FUNCTION "Output Linea e Boxing_2R" : VOID
TITLE =Gestione Output
AUTHOR : MassimoZ
FAMILY : NovaSrl
VERSION : 0.1

BEGIN
NETWORK
TITLE =R0 = Ripristino Emergenza

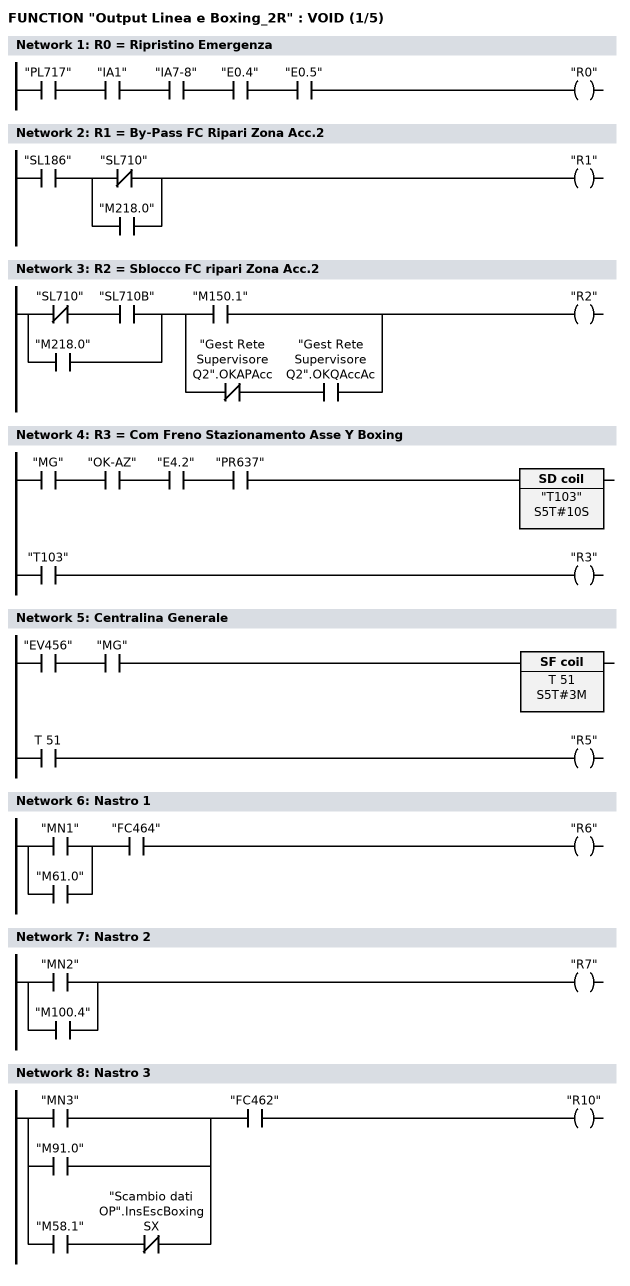
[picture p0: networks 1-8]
      U     "PL717";
      U     "IA1";
      U     "IA7-8";
      U     "E0.4";
      U     "E0.5";
      =     "R0";
NETWORK
TITLE =R1 = By-Pass FC Ripari Zona Acc.2

      U     "SL186";
      U(    ;
      ON    "SL710";
      O     "M218.0";
      )     ;
      =     "R1";
NETWORK
TITLE =R2 = Sblocco FC ripari Zona Acc.2

      U(    ;
      UN    "SL710";
      U     "SL710B";
      O     "M218.0";
      )     ;
      U(    ;
      O     "M150.1";
      O     ;
      UN    "Gest Rete Supervisore Q2".OKAPAcc;
      U     "Gest Rete Supervisore Q2".OKQAccAc;
      )     ;
      =     "R2";
NETWORK
TITLE =R3 = Com Freno Stazionamento Asse Y Boxing

      U     "MG";
      U     "OK-AZ";
      U     "E4.2";
      U     "PR637";
      L     S5T#10S;
      SE    "T103";
      NOP   0;
      NOP   0;
      NOP   0;
      U     "T103";
      =     "R3";
NETWORK
TITLE =Centralina Generale

      U     "EV456";
      U     "MG";
      L     S5T#3M;
      SA    T     51;
      NOP   0;
      NOP   0;
      NOP   0;
      U     T     51;
      =     "R5";
NETWORK
TITLE =Nastro 1

      U(    ;
      O     "MN1";
      O     "M61.0";
      )     ;
      U     "FC464";
      =     "R6";
NETWORK
TITLE =Nastro 2

      O     "MN2";
      O     "M100.4";
      =     "R7";
NETWORK
TITLE =Nastro 3

      U(    ;
      O     "MN3";
      O     "M91.0";
      O     ;
      U     "M58.1";
      UN    "Scambio dati OP".InsEscBoxingSX;
      )     ;
      U     "FC462";
      =     "R10";
NETWORK
TITLE =R11 = Abilitazione Asse X Boxing

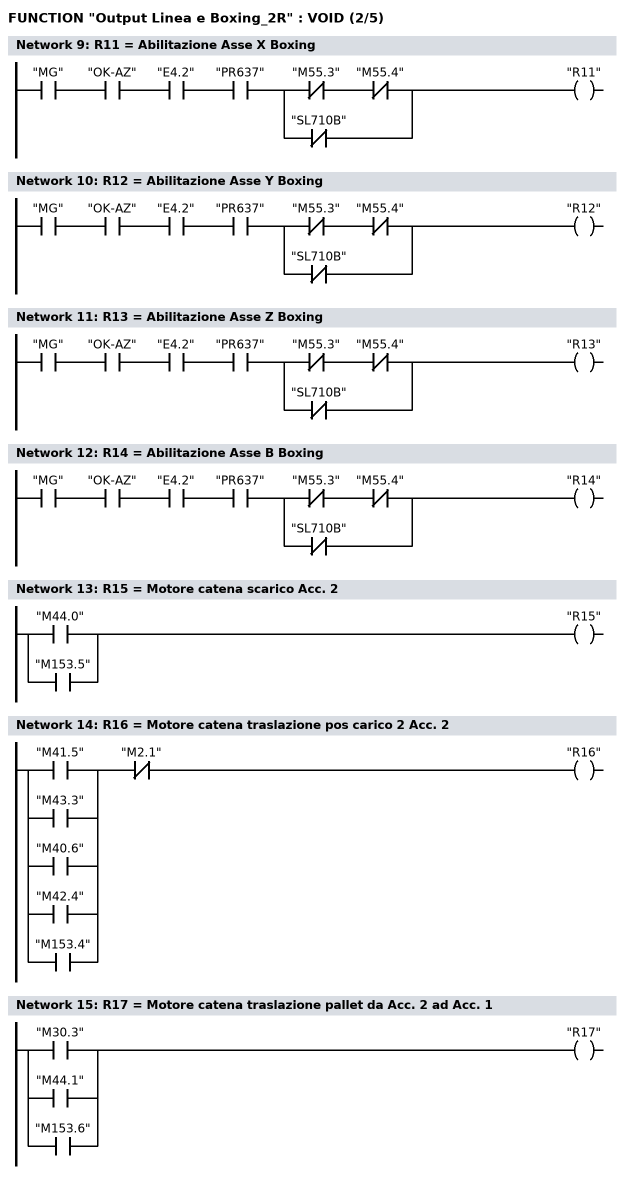
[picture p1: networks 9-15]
      U     "MG";
      U     "OK-AZ";
      U     "E4.2";
      U     "PR637";
      U(    ;
      UN    "M55.3";
      UN    "M55.4";
      ON    "SL710B";
      )     ;
      =     "R11";
NETWORK
TITLE =R12 = Abilitazione Asse Y Boxing

      U     "MG";
      U     "OK-AZ";
      U     "E4.2";
      U     "PR637";
      U(    ;
      UN    "M55.3";
      UN    "M55.4";
      ON    "SL710B";
      )     ;
      =     "R12";
NETWORK
TITLE =R13 = Abilitazione Asse Z Boxing

      U     "MG";
      U     "OK-AZ";
      U     "E4.2";
      U     "PR637";
      U(    ;
      UN    "M55.3";
      UN    "M55.4";
      ON    "SL710B";
      )     ;
      =     "R13";
NETWORK
TITLE =R14 = Abilitazione Asse B Boxing

      U     "MG";
      U     "OK-AZ";
      U     "E4.2";
      U     "PR637";
      U(    ;
      UN    "M55.3";
      UN    "M55.4";
      ON    "SL710B";
      )     ;
      =     "R14";
NETWORK
TITLE =R15 = Motore catena scarico Acc. 2

      O     "M44.0";
      O     "M153.5";
      =     "R15";
NETWORK
TITLE =R16 = Motore catena traslazione pos carico 2 Acc. 2

      U(    ;
      O     "M41.5";
      O     "M43.3";
      O     "M40.6";
      O     "M42.4";
      O     "M153.4";
      )     ;
      UN    "M2.1";
      =     "R16";
NETWORK
TITLE =R17 = Motore catena traslazione pallet da Acc. 2 ad Acc. 1

      O     "M30.3";
      O     "M44.1";
      O     "M153.6";
      =     "R17";
NETWORK
TITLE =R20 = Motore catena traslazione pos carico 2 Acc. 1

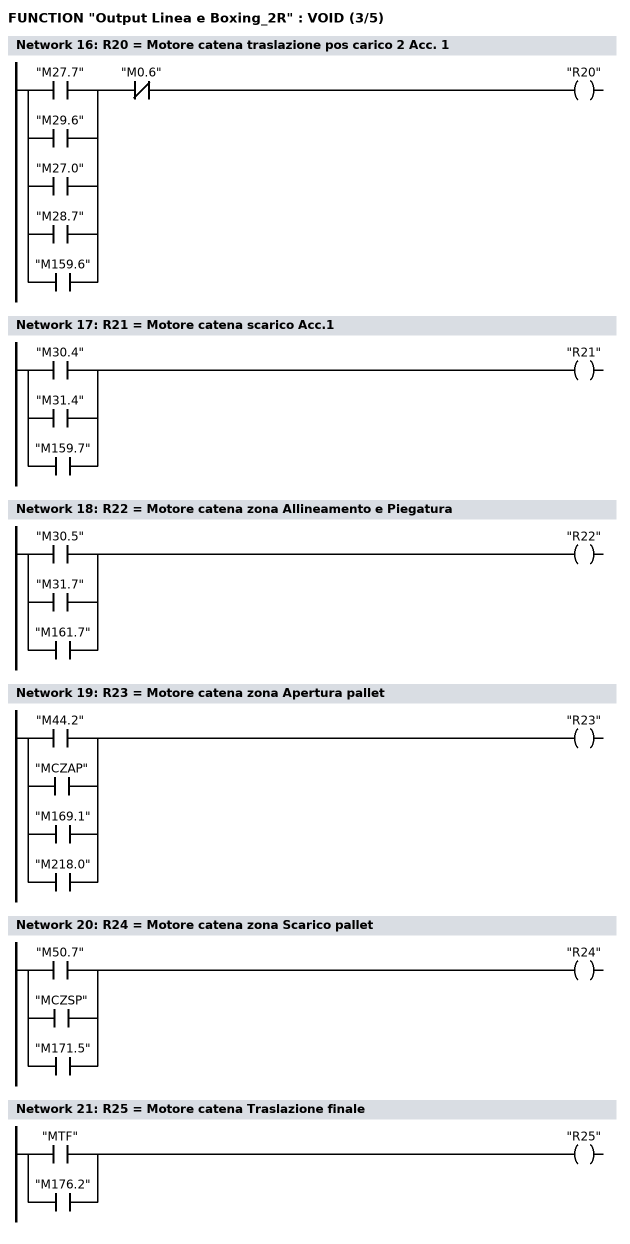
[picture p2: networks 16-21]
      U(    ;
      O     "M27.7";
      O     "M29.6";
      O     "M27.0";
      O     "M28.7";
      O     "M159.6";
      )     ;
      UN    "M0.6";
      =     "R20";
NETWORK
TITLE =R21 = Motore catena scarico Acc.1

      O     "M30.4";
      O     "M31.4";
      O     "M159.7";
      =     "R21";
NETWORK
TITLE =R22 = Motore catena zona Allineamento e Piegatura

      O     "M30.5";
      O     "M31.7";
      O     "M161.7";
      =     "R22";
NETWORK
TITLE =R23 = Motore catena zona Apertura pallet

      O     "M44.2";
      O     "MCZAP";
      O     "M169.1";
      O     "M218.0";
      =     "R23";
NETWORK
TITLE =R24 = Motore catena zona Scarico pallet

      O     "M50.7";
      O     "MCZSP";
      O     "M171.5";
      =     "R24";
NETWORK
TITLE =R25 = Motore catena Traslazione finale

      O     "MTF";
      O     "M176.2";
      =     "R25";
NETWORK
TITLE =R26 = Motore catena Alimentazione accatastatrici

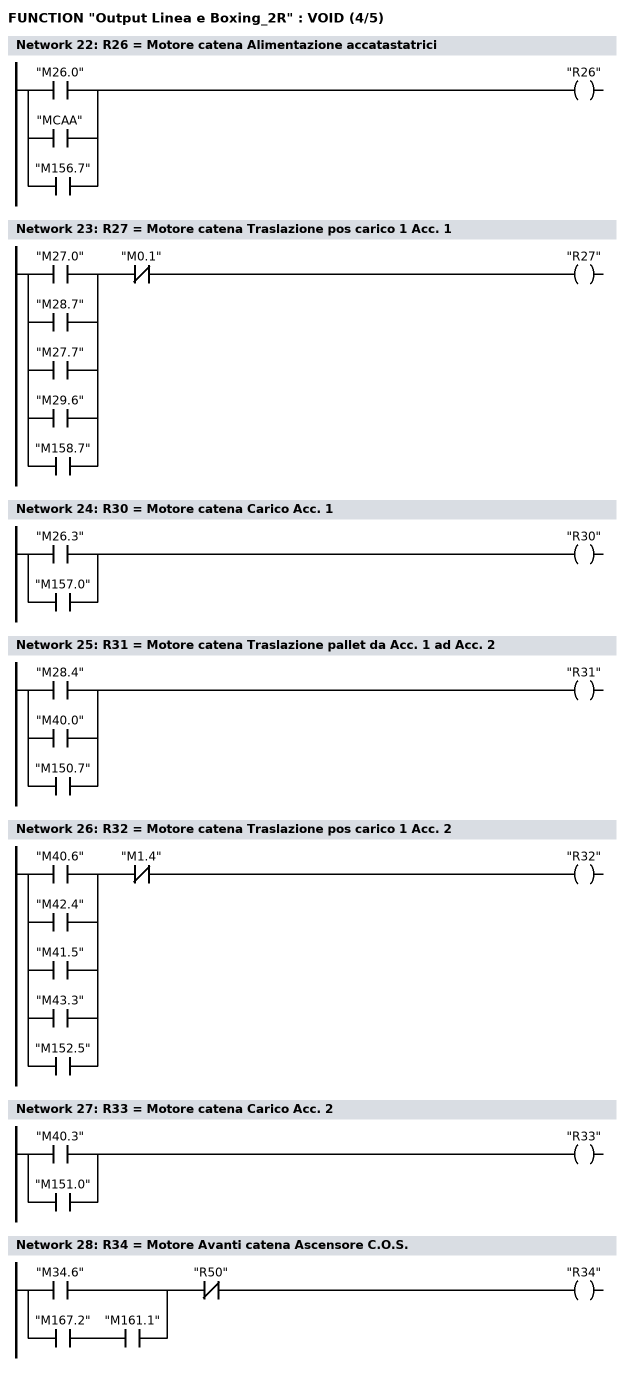
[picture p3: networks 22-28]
      O     "M26.0";
      O     "MCAA";
      O     "M156.7";
      =     "R26";
NETWORK
TITLE =R27 = Motore catena Traslazione pos carico 1 Acc. 1

      U(    ;
      O     "M27.0";
      O     "M28.7";
      O     "M27.7";
      O     "M29.6";
      O     "M158.7";
      )     ;
      UN    "M0.1";
      =     "R27";
NETWORK
TITLE =R30 = Motore catena Carico Acc. 1

      O     "M26.3";
      O     "M157.0";
      =     "R30";
NETWORK
TITLE =R31 = Motore catena Traslazione pallet da Acc. 1 ad Acc. 2

      O     "M28.4";
      O     "M40.0";
      O     "M150.7";
      =     "R31";
NETWORK
TITLE =R32 = Motore catena Traslazione pos carico 1 Acc. 2

      U(    ;
      O     "M40.6";
      O     "M42.4";
      O     "M41.5";
      O     "M43.3";
      O     "M152.5";
      )     ;
      UN    "M1.4";
      =     "R32";
NETWORK
TITLE =R33 = Motore catena Carico Acc. 2

      O     "M40.3";
      O     "M151.0";
      =     "R33";
NETWORK
TITLE =R34 = Motore Avanti catena Ascensore C.O.S.

      U(    ;
      O     "M34.6";
      O     ;
      U     "M167.2";
      U     "M161.1";
      )     ;
      UN    "R50";
      =     "R34";
NETWORK
TITLE =R35 = Motore catena Traslatore scarico SX Avanti

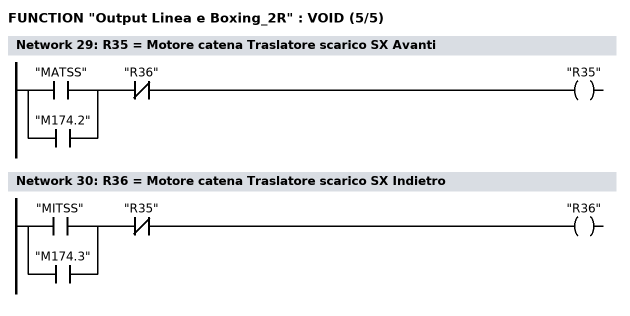
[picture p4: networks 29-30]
      U(    ;
      O     "MATSS";
      O     "M174.2";
      )     ;
      UN    "R36";
      =     "R35";
NETWORK
TITLE =R36 = Motore catena Traslatore scarico SX Indietro

      U(    ;
      O     "MITSS";
      O     "M174.3";
      )     ;
      UN    "R35";
      =     "R36";
NETWORK
TITLE =R37 = Scorta

      CLR   ;
      =     "R37";
NETWORK
TITLE =R40 = Motore catena Traslatore scarico DX Avanti

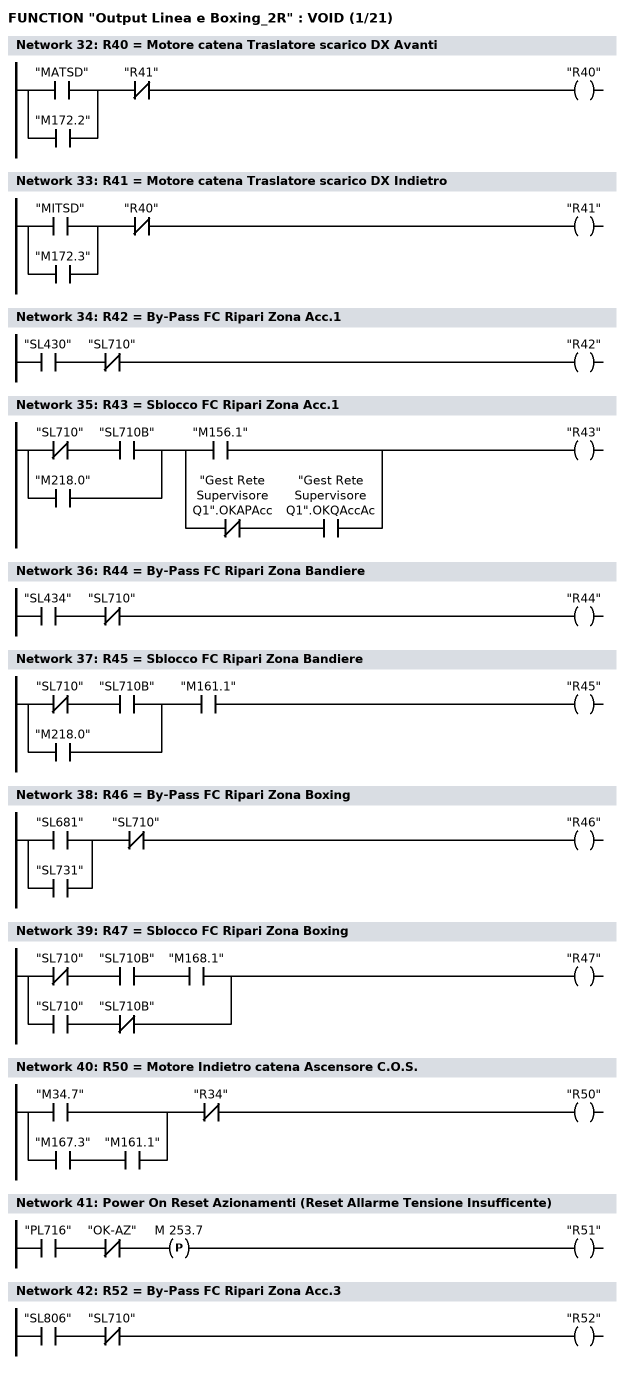
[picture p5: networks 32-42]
      U(    ;
      O     "MATSD";
      O     "M172.2";
      )     ;
      UN    "R41";
      =     "R40";
NETWORK
TITLE =R41 = Motore catena Traslatore scarico DX Indietro

      U(    ;
      O     "MITSD";
      O     "M172.3";
      )     ;
      UN    "R40";
      =     "R41";
NETWORK
TITLE =R42 = By-Pass FC Ripari Zona Acc.1

      U     "SL430";
      UN    "SL710";
      =     "R42";
NETWORK
TITLE =R43 = Sblocco FC Ripari Zona Acc.1

      U(    ;
      UN    "SL710";
      U     "SL710B";
      O     "M218.0";
      )     ;
      U(    ;
      O     "M156.1";
      O     ;
      UN    "Gest Rete Supervisore Q1".OKAPAcc;
      U     "Gest Rete Supervisore Q1".OKQAccAc;
      )     ;
      =     "R43";
NETWORK
TITLE =R44 = By-Pass FC Ripari Zona Bandiere

      U     "SL434";
      UN    "SL710";
      =     "R44";
NETWORK
TITLE =R45 = Sblocco FC Ripari Zona Bandiere

      U(    ;
      UN    "SL710";
      U     "SL710B";
      O     "M218.0";
      )     ;
      U     "M161.1";
      =     "R45";
NETWORK
TITLE =R46 = By-Pass FC Ripari Zona Boxing

      U(    ;
      O     "SL681";
      O     "SL731";
      )     ;
      UN    "SL710";
      =     "R46";
NETWORK
TITLE =R47 = Sblocco FC Ripari Zona Boxing

      UN    "SL710";
      U     "SL710B";
      U     "M168.1";
      O     ;
      U     "SL710";
      UN    "SL710B";
      =     "R47";
NETWORK
TITLE =R50 = Motore Indietro catena Ascensore C.O.S.

      U(    ;
      O     "M34.7";
      O     ;
      U     "M167.3";
      U     "M161.1";
      )     ;
      UN    "R34";
      =     "R50";
NETWORK
TITLE =Power On Reset Azionamenti (Reset Allarme Tensione Insufficente)

      U     "PL716";
      UN    "OK-AZ";
      FP    M    253.7;
      =     "R51";
NETWORK
TITLE =R52 = By-Pass FC Ripari Zona Acc.3

      U     "SL806";
      UN    "SL710";
      =     "R52";
NETWORK
TITLE =R50 = Sblocco FC Ripari Zona Acc.3

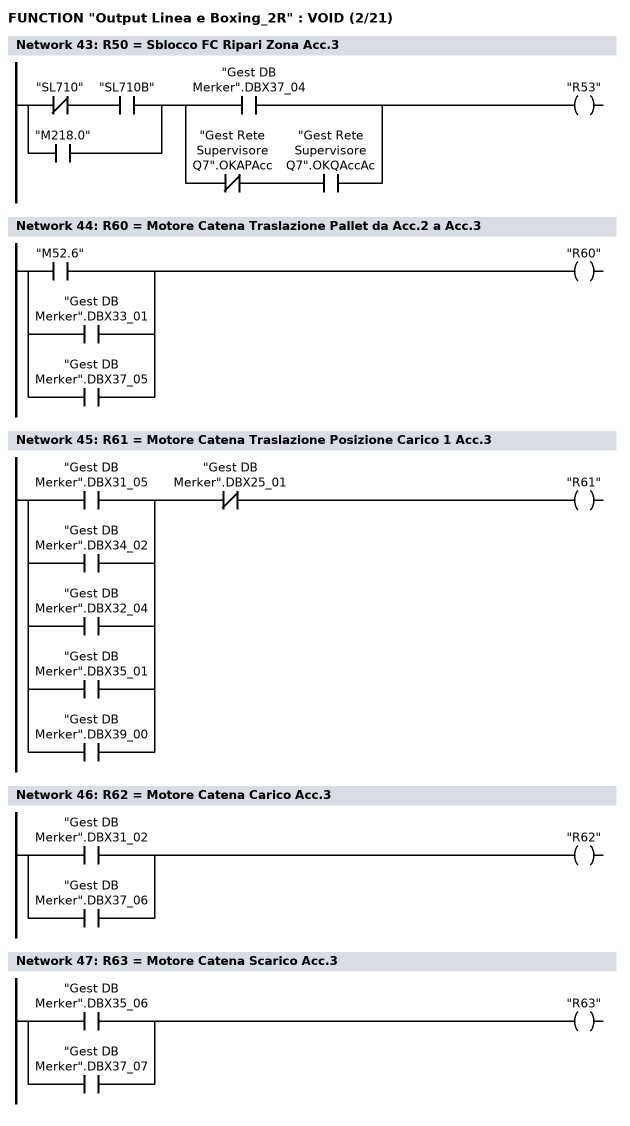
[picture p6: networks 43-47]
      U(    ;
      UN    "SL710";
      U     "SL710B";
      O     "M218.0";
      )     ;
      U(    ;
      O     "Gest DB Merker".DBX37_04;
      O     ;
      UN    "Gest Rete Supervisore Q7".OKAPAcc;
      U     "Gest Rete Supervisore Q7".OKQAccAc;
      )     ;
      =     "R53";
NETWORK
TITLE =R60 = Motore Catena Traslazione Pallet da Acc.2 a Acc.3

      O     "M52.6";
      O     "Gest DB Merker".DBX33_01;
      O     "Gest DB Merker".DBX37_05;
      =     "R60";
NETWORK
TITLE =R61 = Motore Catena Traslazione Posizione Carico 1 Acc.3

      U(    ;
      O     "Gest DB Merker".DBX31_05;
      O     "Gest DB Merker".DBX34_02;
      O     "Gest DB Merker".DBX32_04;
      O     "Gest DB Merker".DBX35_01;
      O     "Gest DB Merker".DBX39_00;
      )     ;
      UN    "Gest DB Merker".DBX25_01;
      =     "R61";
NETWORK
TITLE =R62 = Motore Catena Carico Acc.3

      O     "Gest DB Merker".DBX31_02;
      O     "Gest DB Merker".DBX37_06;
      =     "R62";
NETWORK
TITLE =R63 = Motore Catena Scarico Acc.3

      O     "Gest DB Merker".DBX35_06;
      O     "Gest DB Merker".DBX37_07;
      =     "R63";
NETWORK
TITLE =R64 = Motore Catena Traslazione Posizione Carico 2 Acc.3

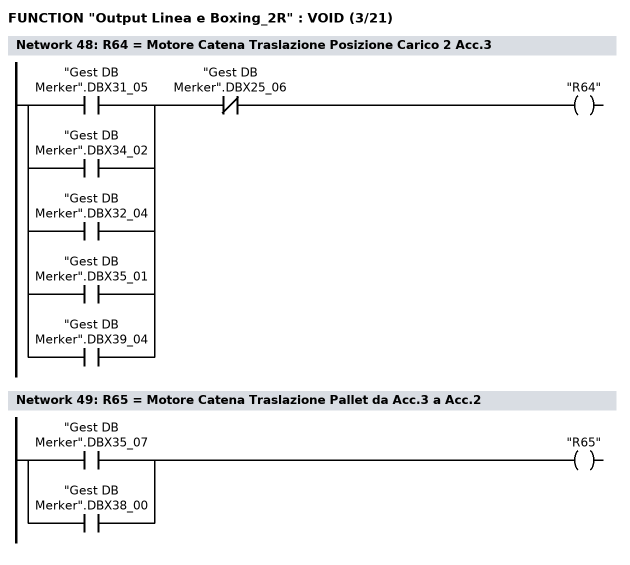
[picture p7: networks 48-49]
      U(    ;
      O     "Gest DB Merker".DBX31_05;
      O     "Gest DB Merker".DBX34_02;
      O     "Gest DB Merker".DBX32_04;
      O     "Gest DB Merker".DBX35_01;
      O     "Gest DB Merker".DBX39_04;
      )     ;
      UN    "Gest DB Merker".DBX25_06;
      =     "R64";
NETWORK
TITLE =R65 = Motore Catena Traslazione Pallet da Acc.3 a Acc.2

      O     "Gest DB Merker".DBX35_07;
      O     "Gest DB Merker".DBX38_00;
      =     "R65";
NETWORK
TITLE =Traslazione Pinze Polso Avanti

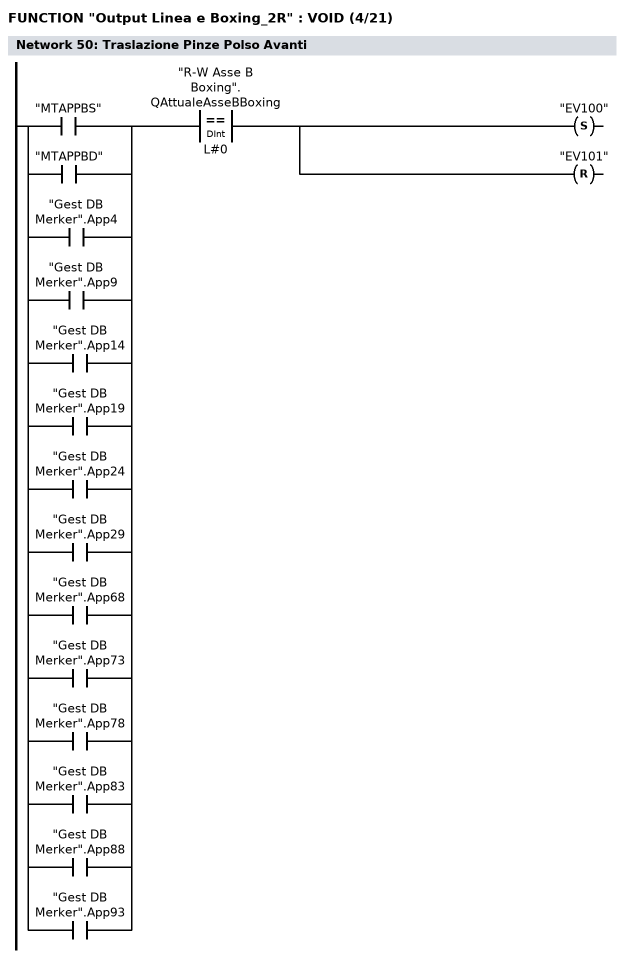
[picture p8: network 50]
      U(    ;
      O     "MTAPPBS";
      O     "MTAPPBD";
      O     "Gest DB Merker".App4;
      O     "Gest DB Merker".App9;
      O     "Gest DB Merker".App14;
      O     "Gest DB Merker".App19;
      O     "Gest DB Merker".App24;
      O     "Gest DB Merker".App29;
      O     "Gest DB Merker".App68;
      O     "Gest DB Merker".App73;
      O     "Gest DB Merker".App78;
      O     "Gest DB Merker".App83;
      O     "Gest DB Merker".App88;
      O     "Gest DB Merker".App93;
      )     ;
      U(    ;
      L     "R-W Asse B Boxing".QAttualeAsseBBoxing;
      L     L#0;
      ==D   ;
      )     ;
      S     "EV100";
      R     "EV101";
NETWORK
TITLE =Traslazione Pinze Polso Indietro

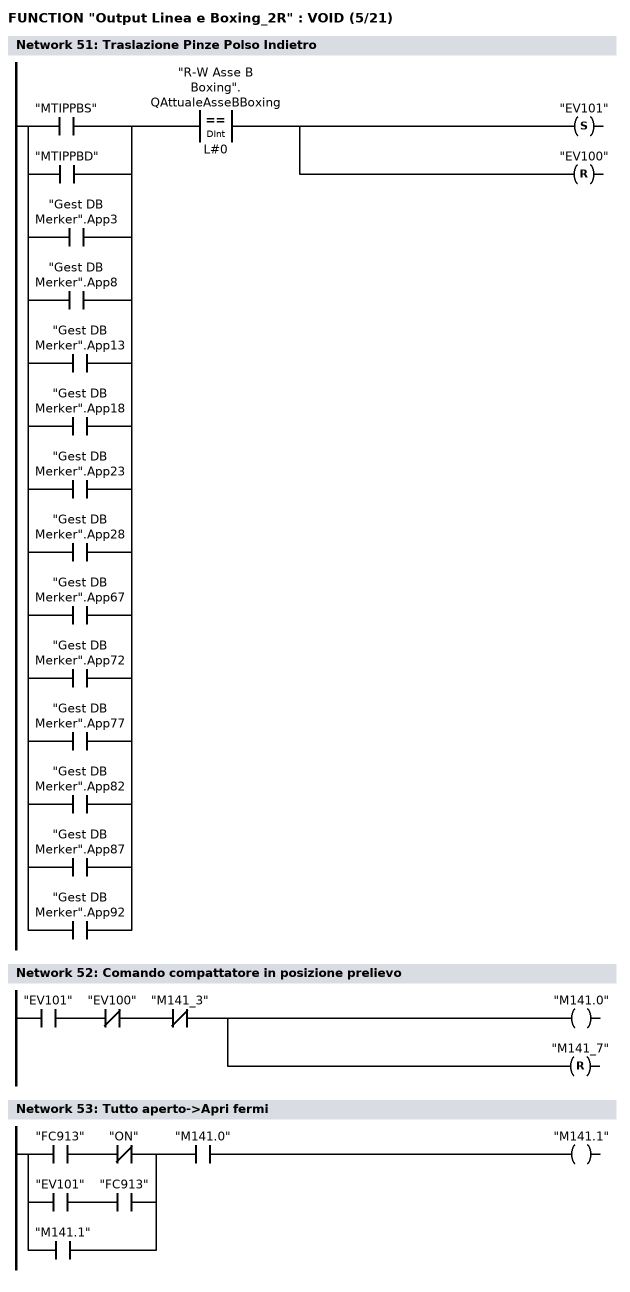
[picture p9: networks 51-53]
      U(    ;
      O     "MTIPPBS";
      O     "MTIPPBD";
      O     "Gest DB Merker".App3;
      O     "Gest DB Merker".App8;
      O     "Gest DB Merker".App13;
      O     "Gest DB Merker".App18;
      O     "Gest DB Merker".App23;
      O     "Gest DB Merker".App28;
      O     "Gest DB Merker".App67;
      O     "Gest DB Merker".App72;
      O     "Gest DB Merker".App77;
      O     "Gest DB Merker".App82;
      O     "Gest DB Merker".App87;
      O     "Gest DB Merker".App92;
      )     ;
      U(    ;
      L     "R-W Asse B Boxing".QAttualeAsseBBoxing;
      L     L#0;
      ==D   ;
      )     ;
      S     "EV101";
      R     "EV100";
NETWORK
TITLE =Comando compattatore in posizione prelievo

      U     "EV101";
      UN    "EV100";
      UN    "M141_3";
      =     "M141.0";
      R     "M141_7";
NETWORK
TITLE =Tutto aperto->Apri fermi

      U(    ;
      U     "FC913";
      UN    "ON";
      O     ;
      U     "EV101";
      U     "FC913";
      O     "M141.1";
      )     ;
      U     "M141.0";
      =     "M141.1";
NETWORK
TITLE =Fermi aperti->richiudi

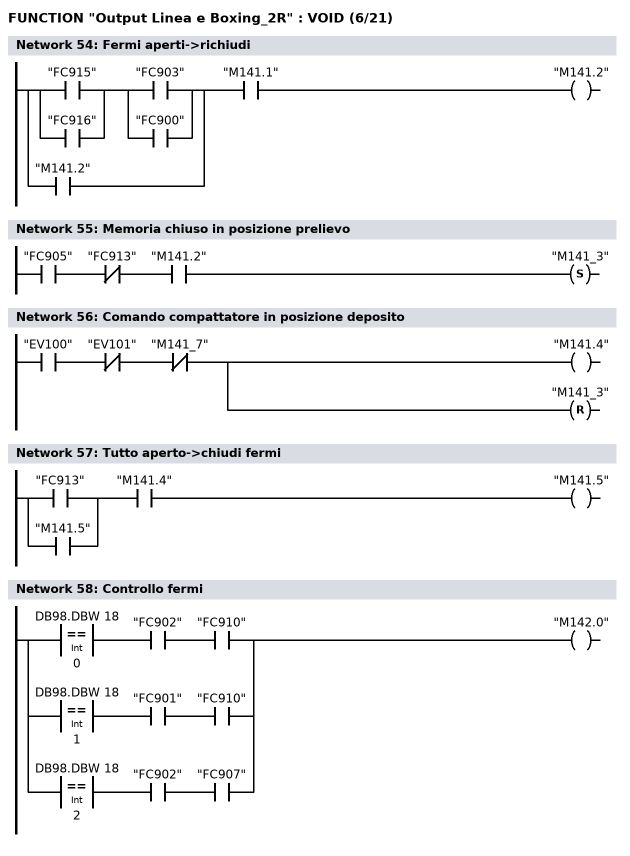
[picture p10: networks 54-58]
      U(    ;
      U(    ;
      O     "FC915";
      O     "FC916";
      )     ;
      U(    ;
      O     "FC903";
      O     "FC900";
      )     ;
      O     "M141.2";
      )     ;
      U     "M141.1";
      =     "M141.2";
NETWORK
TITLE =Memoria chiuso in posizione prelievo

      U     "FC905";
      UN    "FC913";
      U     "M141.2";
      S     "M141_3";
NETWORK
TITLE =Comando compattatore in posizione deposito

      U     "EV100";
      UN    "EV101";
      UN    "M141_7";
      =     "M141.4";
      R     "M141_3";
NETWORK
TITLE =Tutto aperto->chiudi fermi

      U(    ;
      O     "FC913";
      O     "M141.5";
      )     ;
      U     "M141.4";
      =     "M141.5";
NETWORK
TITLE =Controllo fermi

      U(    ;
      L     DB98.DBW   18;
      L     0;
      ==I   ;
      )     ;
      U     "FC902";
      U     "FC910";
      O     ;
      U(    ;
      L     DB98.DBW   18;
      L     1;
      ==I   ;
      )     ;
      U     "FC901";
      U     "FC910";
      O     ;
      U(    ;
      L     DB98.DBW   18;
      L     2;
      ==I   ;
      )     ;
      U     "FC902";
      U     "FC907";
      =     "M142.0";
NETWORK
TITLE =Controllo rotazione pinze

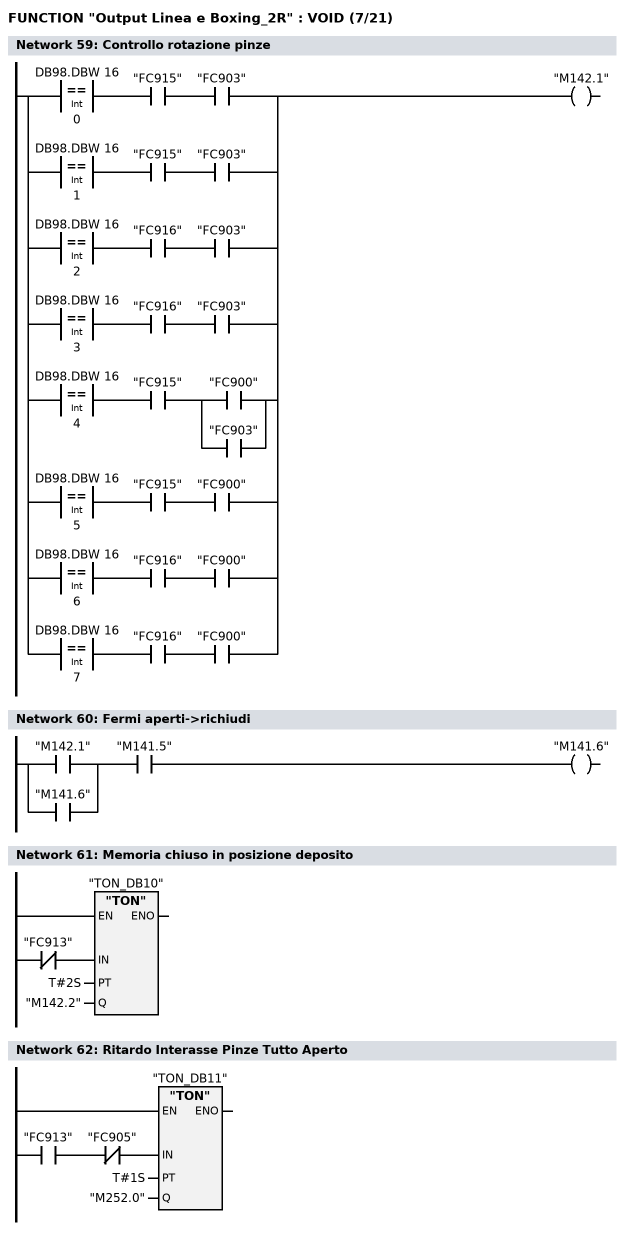
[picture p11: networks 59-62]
      U(    ;
      L     DB98.DBW   16;
      L     0;
      ==I   ;
      )     ;
      U     "FC915";
      U     "FC903";
      O     ;
      U(    ;
      L     DB98.DBW   16;
      L     1;
      ==I   ;
      )     ;
      U     "FC915";
      U     "FC903";
      O     ;
      U(    ;
      L     DB98.DBW   16;
      L     2;
      ==I   ;
      )     ;
      U     "FC916";
      U     "FC903";
      O     ;
      U(    ;
      L     DB98.DBW   16;
      L     3;
      ==I   ;
      )     ;
      U     "FC916";
      U     "FC903";
      O     ;
      U(    ;
      L     DB98.DBW   16;
      L     4;
      ==I   ;
      )     ;
      U     "FC915";
      U(    ;
      O     "FC900";
      O     "FC903";
      )     ;
      O     ;
      U(    ;
      L     DB98.DBW   16;
      L     5;
      ==I   ;
      )     ;
      U     "FC915";
      U     "FC900";
      O     ;
      U(    ;
      L     DB98.DBW   16;
      L     6;
      ==I   ;
      )     ;
      U     "FC916";
      U     "FC900";
      O     ;
      U(    ;
      L     DB98.DBW   16;
      L     7;
      ==I   ;
      )     ;
      U     "FC916";
      U     "FC900";
      =     "M142.1";
NETWORK
TITLE =Fermi aperti->richiudi

      U(    ;
      O     "M142.1";
      O     "M141.6";
      )     ;
      U     "M141.5";
      =     "M141.6";
NETWORK
TITLE =Memoria chiuso in posizione deposito

      UN    "FC913";
      =     L      0.0;
      BLD   103;
      CALL "TON" , "TON_DB10" (
           IN                       := L      0.0,
           PT                       := T#2S,
           Q                        := "M142.2");

      NOP   0;
NETWORK
TITLE =Ritardo Interasse Pinze Tutto Aperto

      U     "FC913";
      UN    "FC905";
      =     L      0.0;
      BLD   103;
      CALL "TON" , "TON_DB11" (
           IN                       := L      0.0,
           PT                       := T#1S,
           Q                        := "M252.0");

      NOP   0;
NETWORK
TITLE =Memoria compattatore maipol. chiuso in posizione deposito

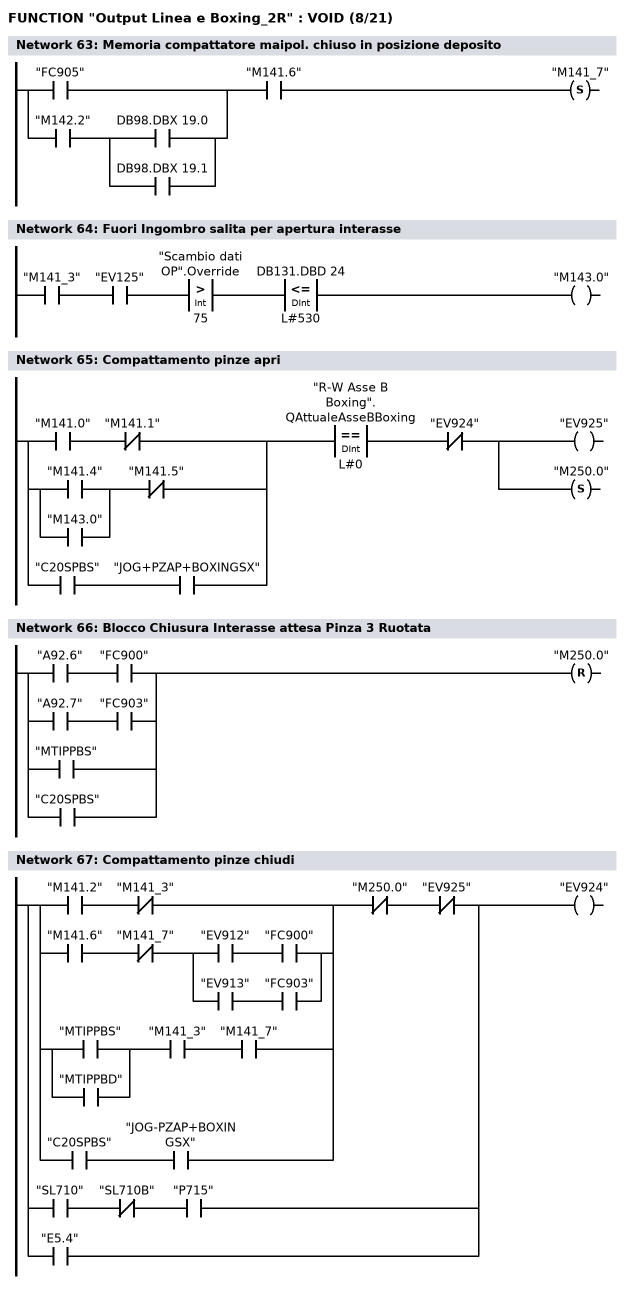
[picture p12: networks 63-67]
      U(    ;
      O     "FC905";
      O     ;
      U     "M142.2";
      U(    ;
      O     DB98.DBX   19.0;
      O     DB98.DBX   19.1;
      )     ;
      )     ;
      U     "M141.6";
      S     "M141_7";
NETWORK
TITLE =Fuori Ingombro salita per apertura interasse

      U     "M141_3";
      U     "EV125";
      U(    ;
      L     "Scambio dati OP".Override;
      L     75;
      >I    ;
      )     ;
      U(    ;
      L     DB131.DBD   24;
      L     L#530;
      <=D   ;
      )     ;
      =     "M143.0";
NETWORK
TITLE =Compattamento pinze apri

      U(    ;
      U     "M141.0";
      UN    "M141.1";
      O     ;
      U(    ;
      O     "M141.4";
      O     "M143.0";
      )     ;
      UN    "M141.5";
      O     ;
      U     "C20SPBS";
      U     "JOG+PZAP+BOXINGSX";
      )     ;
      U(    ;
      L     "R-W Asse B Boxing".QAttualeAsseBBoxing;
      L     L#0;
      ==D   ;
      )     ;
      UN    "EV924";
      =     "EV925";
      S     "M250.0";
NETWORK
TITLE =Blocco Chiusura Interasse attesa Pinza 3 Ruotata

      U     "A92.6";
      U     "FC900";
      O     ;
      U     "A92.7";
      U     "FC903";
      O     "MTIPPBS";
      O     "C20SPBS";
      R     "M250.0";
NETWORK
TITLE =Compattamento pinze chiudi

      U(    ;
      U     "M141.2";
      UN    "M141_3";
      O     ;
      U     "M141.6";
      UN    "M141_7";
      U(    ;
      U     "EV912";
      U     "FC900";
      O     ;
      U     "EV913";
      U     "FC903";
      )     ;
      O     ;
      U(    ;
      O     "MTIPPBS";
      O     "MTIPPBD";
      )     ;
      U     "M141_3";
      U     "M141_7";
      O     ;
      U     "C20SPBS";
      U     "JOG-PZAP+BOXINGSX";
      )     ;
      UN    "M250.0";
      UN    "EV925";
      O     ;
      U     "SL710";
      UN    "SL710B";
      U     "P715";
      O     "E5.4";
      =     "EV924";
NETWORK
TITLE =Fermi laterali compattamento apri

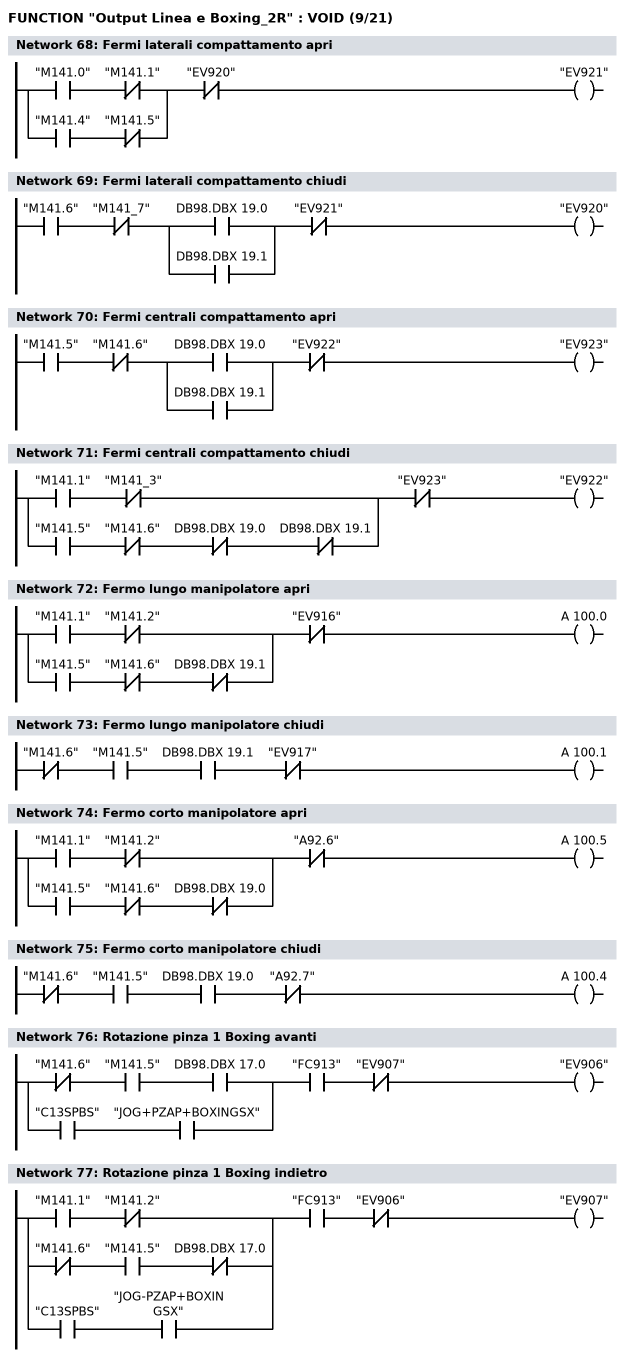
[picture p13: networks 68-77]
      U(    ;
      U     "M141.0";
      UN    "M141.1";
      O     ;
      U     "M141.4";
      UN    "M141.5";
      )     ;
      UN    "EV920";
      =     "EV921";
NETWORK
TITLE =Fermi laterali compattamento chiudi

      U     "M141.6";
      UN    "M141_7";
      U(    ;
      O     DB98.DBX   19.0;
      O     DB98.DBX   19.1;
      )     ;
      UN    "EV921";
      =     "EV920";
NETWORK
TITLE =Fermi centrali compattamento apri

      U     "M141.5";
      UN    "M141.6";
      U(    ;
      O     DB98.DBX   19.0;
      O     DB98.DBX   19.1;
      )     ;
      UN    "EV922";
      =     "EV923";
NETWORK
TITLE =Fermi centrali compattamento chiudi

      U(    ;
      U     "M141.1";
      UN    "M141_3";
      O     ;
      U     "M141.5";
      UN    "M141.6";
      UN    DB98.DBX   19.0;
      UN    DB98.DBX   19.1;
      )     ;
      UN    "EV923";
      =     "EV922";
NETWORK
TITLE =Fermo lungo manipolatore apri

      U(    ;
      U     "M141.1";
      UN    "M141.2";
      O     ;
      U     "M141.5";
      UN    "M141.6";
      UN    DB98.DBX   19.1;
      )     ;
      UN    "EV916";
      =     A    100.0;
NETWORK
TITLE =Fermo lungo manipolatore chiudi

      UN    "M141.6";
      U     "M141.5";
      U     DB98.DBX   19.1;
      UN    "EV917";
      =     A    100.1;
NETWORK
TITLE =Fermo corto manipolatore apri

      U(    ;
      U     "M141.1";
      UN    "M141.2";
      O     ;
      U     "M141.5";
      UN    "M141.6";
      UN    DB98.DBX   19.0;
      )     ;
      UN    "A92.6";
      =     A    100.5;
NETWORK
TITLE =Fermo corto manipolatore chiudi

      UN    "M141.6";
      U     "M141.5";
      U     DB98.DBX   19.0;
      UN    "A92.7";
      =     A    100.4;
NETWORK
TITLE =Rotazione pinza 1 Boxing avanti

      U(    ;
      UN    "M141.6";
      U     "M141.5";
      U     DB98.DBX   17.0;
      O     ;
      U     "C13SPBS";
      U     "JOG+PZAP+BOXINGSX";
      )     ;
      U     "FC913";
      UN    "EV907";
      =     "EV906";
NETWORK
TITLE =Rotazione pinza 1 Boxing indietro

      U(    ;
      U     "M141.1";
      UN    "M141.2";
      O     ;
      UN    "M141.6";
      U     "M141.5";
      UN    DB98.DBX   17.0;
      O     ;
      U     "C13SPBS";
      U     "JOG-PZAP+BOXINGSX";
      )     ;
      U     "FC913";
      UN    "EV906";
      =     "EV907";
NETWORK
TITLE =Rotazione pinza 2 Boxing avanti

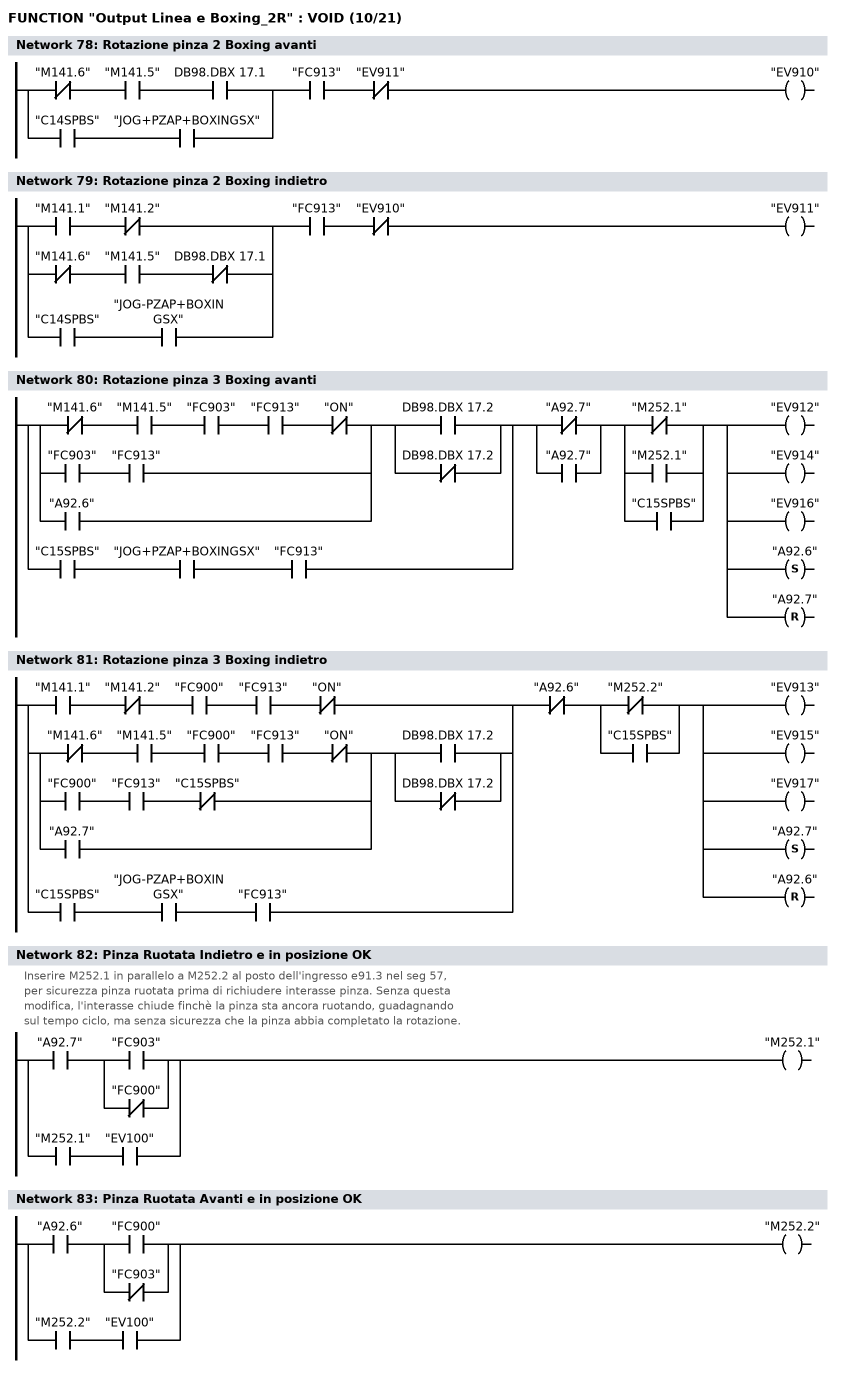
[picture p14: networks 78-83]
      U(    ;
      UN    "M141.6";
      U     "M141.5";
      U     DB98.DBX   17.1;
      O     ;
      U     "C14SPBS";
      U     "JOG+PZAP+BOXINGSX";
      )     ;
      U     "FC913";
      UN    "EV911";
      =     "EV910";
NETWORK
TITLE =Rotazione pinza 2 Boxing indietro

      U(    ;
      U     "M141.1";
      UN    "M141.2";
      O     ;
      UN    "M141.6";
      U     "M141.5";
      UN    DB98.DBX   17.1;
      O     ;
      U     "C14SPBS";
      U     "JOG-PZAP+BOXINGSX";
      )     ;
      U     "FC913";
      UN    "EV910";
      =     "EV911";
NETWORK
TITLE =Rotazione pinza 3 Boxing avanti

      U(    ;
      U(    ;
      UN    "M141.6";
      U     "M141.5";
      U     "FC903";
      U     "FC913";
      UN    "ON";
      O     ;
      U     "FC903";
      U     "FC913";
      O     "A92.6";
      )     ;
      U(    ;
      O     DB98.DBX   17.2;
      ON    DB98.DBX   17.2;
      )     ;
      O     ;
      U     "C15SPBS";
      U     "JOG+PZAP+BOXINGSX";
      U     "FC913";
      )     ;
      U(    ;
      ON    "A92.7";
      O     "A92.7";
      )     ;
      U(    ;
      ON    "M252.1";
      O     "M252.1";
      O     "C15SPBS";
      )     ;
      =     "EV912";
      =     "EV914";
      =     "EV916";
      S     "A92.6";
      R     "A92.7";
NETWORK
TITLE =Rotazione pinza 3 Boxing indietro

      U(    ;
      U     "M141.1";
      UN    "M141.2";
      U     "FC900";
      U     "FC913";
      UN    "ON";
      O     ;
      U(    ;
      UN    "M141.6";
      U     "M141.5";
      U     "FC900";
      U     "FC913";
      UN    "ON";
      O     ;
      U     "FC900";
      U     "FC913";
      UN    "C15SPBS";
      O     "A92.7";
      )     ;
      U(    ;
      O     DB98.DBX   17.2;
      ON    DB98.DBX   17.2;
      )     ;
      O     ;
      U     "C15SPBS";
      U     "JOG-PZAP+BOXINGSX";
      U     "FC913";
      )     ;
      UN    "A92.6";
      U(    ;
      ON    "M252.2";
      O     "C15SPBS";
      )     ;
      =     "EV913";
      =     "EV915";
      =     "EV917";
      S     "A92.7";
      R     "A92.6";
NETWORK
TITLE =Pinza Ruotata Indietro e in posizione OK
//Inserire M252.1 in parallelo a M252.2 al posto dell'ingresso e91.3 nel seg 57,
//per sicurezza pinza ruotata prima di richiudere interasse pinza. Senza questa
//modifica, l'interasse chiude finchè la pinza sta ancora ruotando, guadagnando
//sul tempo ciclo, ma senza sicurezza che la pinza abbia completato la rotazione.
      U     "A92.7";
      U(    ;
      O     "FC903";
      ON    "FC900";
      )     ;
      O     ;
      U     "M252.1";
      U     "EV100";
      =     "M252.1";
NETWORK
TITLE =Pinza Ruotata Avanti e in posizione OK

      U     "A92.6";
      U(    ;
      O     "FC900";
      ON    "FC903";
      )     ;
      O     ;
      U     "M252.2";
      U     "EV100";
      =     "M252.2";
NETWORK
TITLE =Apertura Regolazione Pinze Polso

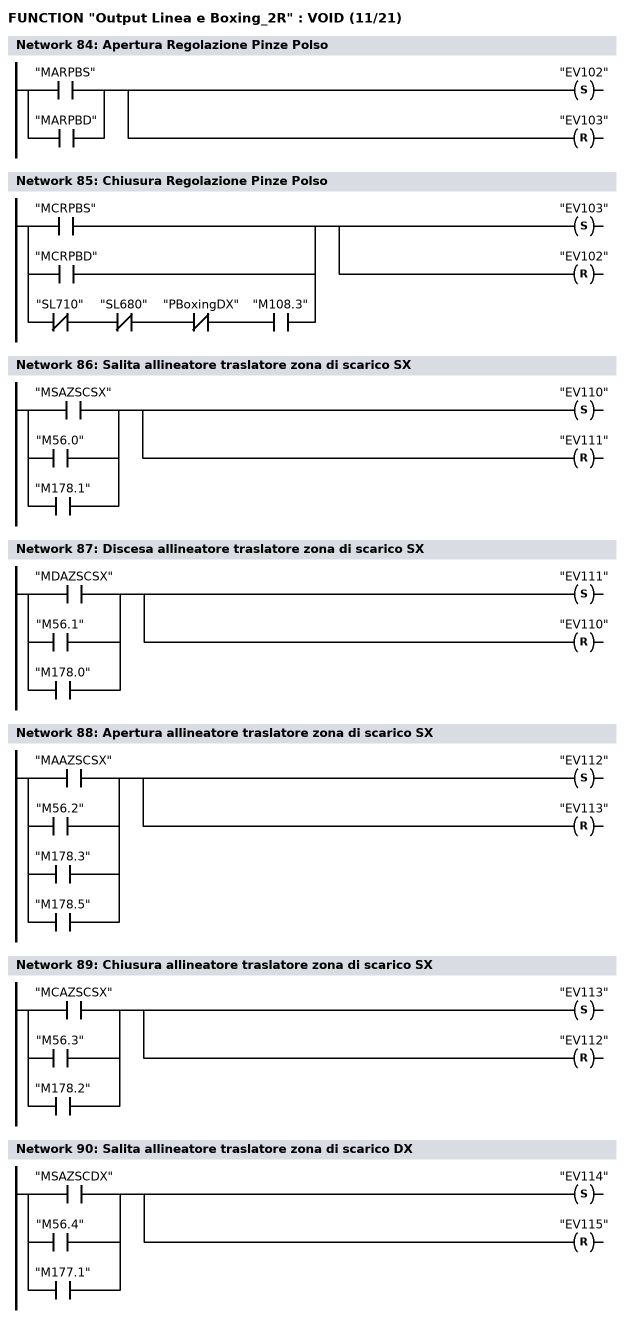
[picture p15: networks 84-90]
      O     "MARPBS";
      O     "MARPBD";
      S     "EV102";
      R     "EV103";
NETWORK
TITLE =Chiusura Regolazione Pinze Polso

      O     "MCRPBS";
      O     "MCRPBD";
      O     ;
      UN    "SL710";
      UN    "SL680";
      UN    "PBoxingDX";
      U     "M108.3";
      S     "EV103";
      R     "EV102";
NETWORK
TITLE =Salita allineatore traslatore zona di scarico SX

      O     "MSAZSCSX";
      O     "M56.0";
      O     "M178.1";
      S     "EV110";
      R     "EV111";
NETWORK
TITLE =Discesa allineatore traslatore zona di scarico SX

      O     "MDAZSCSX";
      O     "M56.1";
      O     "M178.0";
      S     "EV111";
      R     "EV110";
NETWORK
TITLE =Apertura allineatore traslatore zona di scarico SX

      O     "MAAZSCSX";
      O     "M56.2";
      O     "M178.3";
      O     "M178.5";
      S     "EV112";
      R     "EV113";
NETWORK
TITLE =Chiusura allineatore traslatore zona di scarico SX

      O     "MCAZSCSX";
      O     "M56.3";
      O     "M178.2";
      S     "EV113";
      R     "EV112";
NETWORK
TITLE =Salita allineatore traslatore zona di scarico DX

      O     "MSAZSCDX";
      O     "M56.4";
      O     "M177.1";
      S     "EV114";
      R     "EV115";
NETWORK
TITLE =Discesa allineatore traslatore zona di scarico DX

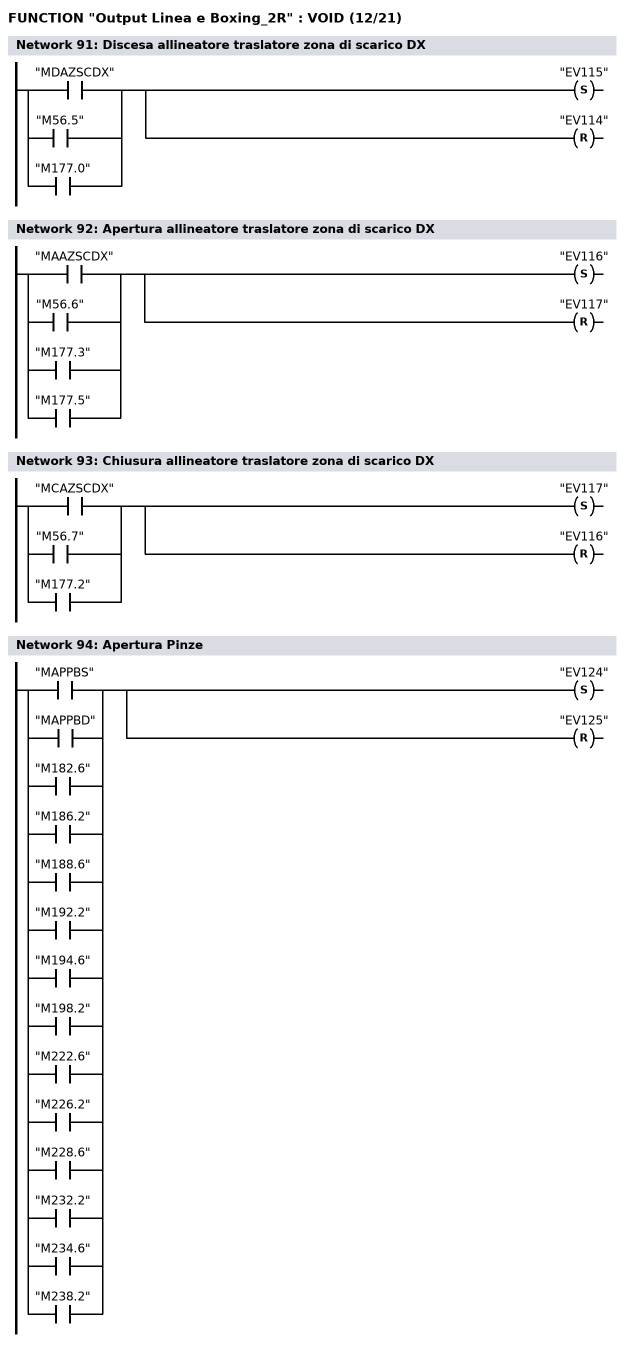
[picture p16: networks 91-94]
      O     "MDAZSCDX";
      O     "M56.5";
      O     "M177.0";
      S     "EV115";
      R     "EV114";
NETWORK
TITLE =Apertura allineatore traslatore zona di scarico DX

      O     "MAAZSCDX";
      O     "M56.6";
      O     "M177.3";
      O     "M177.5";
      S     "EV116";
      R     "EV117";
NETWORK
TITLE =Chiusura allineatore traslatore zona di scarico DX

      O     "MCAZSCDX";
      O     "M56.7";
      O     "M177.2";
      S     "EV117";
      R     "EV116";
NETWORK
TITLE =Apertura Pinze

      O     "MAPPBS";
      O     "MAPPBD";
      O     "M182.6";
      O     "M186.2";
      O     "M188.6";
      O     "M192.2";
      O     "M194.6";
      O     "M198.2";
      O     "M222.6";
      O     "M226.2";
      O     "M228.6";
      O     "M232.2";
      O     "M234.6";
      O     "M238.2";
      S     "EV124";
      R     "EV125";
NETWORK
TITLE =Chiusura Pinze

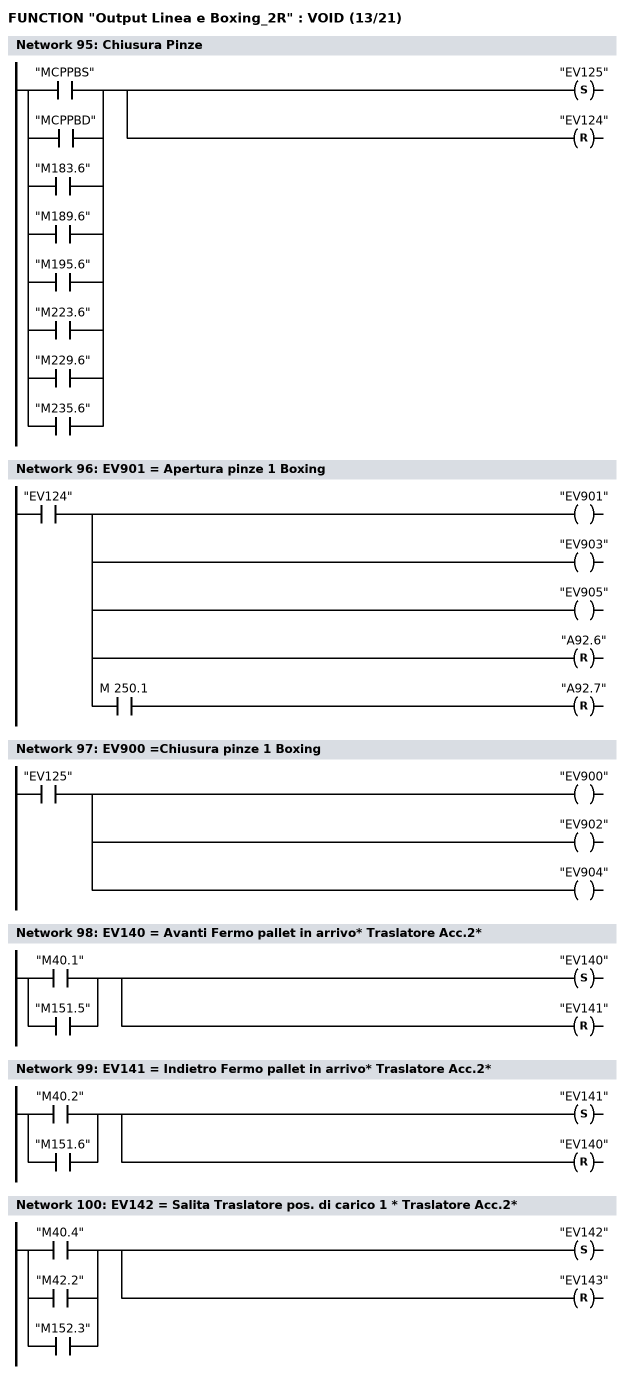
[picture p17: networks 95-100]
      O     "MCPPBS";
      O     "MCPPBD";
      O     "M183.6";
      O     "M189.6";
      O     "M195.6";
      O     "M223.6";
      O     "M229.6";
      O     "M235.6";
      S     "EV125";
      R     "EV124";
NETWORK
TITLE =EV901 = Apertura pinze 1 Boxing

      U     "EV124";
      =     L      0.0;
      U     L      0.0;
      BLD   102;
      =     "EV901";
      U     L      0.0;
      BLD   102;
      =     "EV903";
      U     L      0.0;
      BLD   102;
      =     "EV905";
      U     L      0.0;
      BLD   102;
      R     "A92.6";
      U     L      0.0;
      U     M    250.1;
      R     "A92.7";
NETWORK
TITLE =EV900 =Chiusura pinze 1 Boxing

      U     "EV125";
      =     "EV900";
      =     "EV902";
      =     "EV904";
NETWORK
TITLE =EV140 = Avanti Fermo pallet in arrivo* Traslatore Acc.2*

      O     "M40.1";
      O     "M151.5";

      S     "EV140";
      R     "EV141";
NETWORK
TITLE =EV141 = Indietro Fermo pallet in arrivo* Traslatore Acc.2*

      O     "M40.2";
      O     "M151.6";
      S     "EV141";
      R     "EV140";
NETWORK
TITLE =EV142 = Salita Traslatore pos. di carico 1 * Traslatore Acc.2*

      O     "M40.4";
      O     "M42.2";
      O     "M152.3";
      S     "EV142";
      R     "EV143";
NETWORK
TITLE =EV143 = Discesa Traslatore pos. di carico 1 * Traslatore Acc.2*

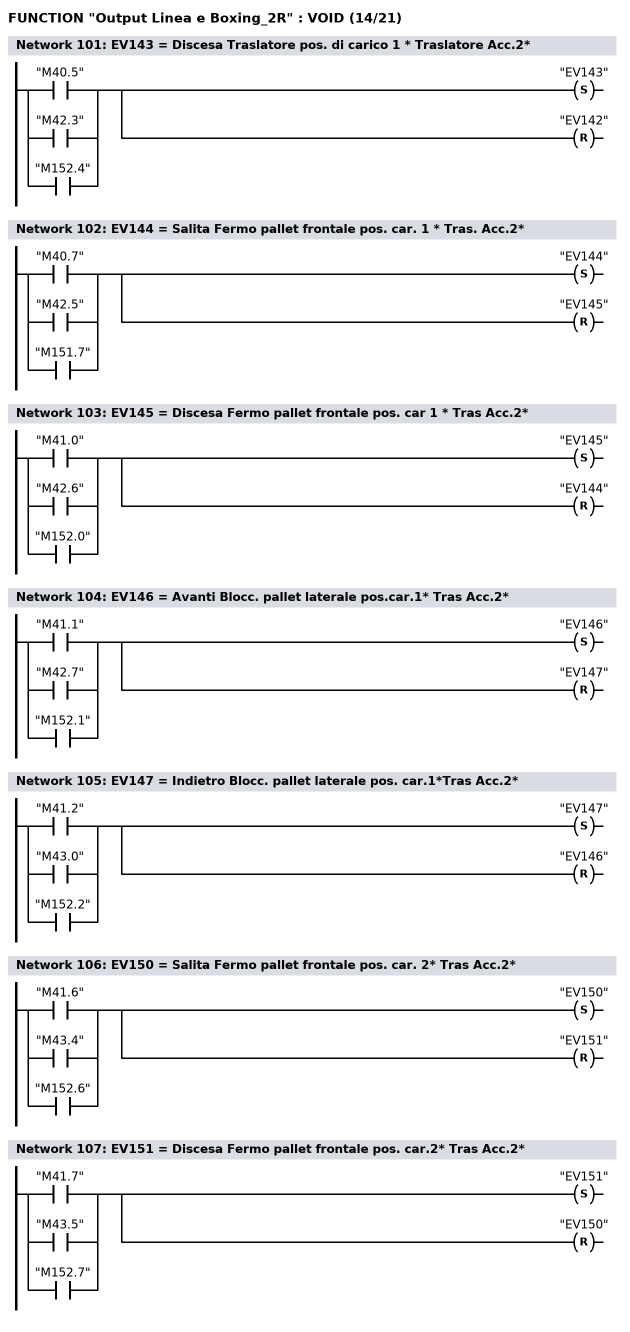
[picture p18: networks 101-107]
      O     "M40.5";
      O     "M42.3";
      O     "M152.4";
      S     "EV143";
      R     "EV142";
NETWORK
TITLE =EV144 = Salita Fermo pallet frontale pos. car. 1 * Tras. Acc.2*

      O     "M40.7";
      O     "M42.5";
      O     "M151.7";
      S     "EV144";
      R     "EV145";
NETWORK
TITLE =EV145 = Discesa Fermo pallet frontale pos. car 1 * Tras Acc.2*

      O     "M41.0";
      O     "M42.6";
      O     "M152.0";
      S     "EV145";
      R     "EV144";
NETWORK
TITLE =EV146 = Avanti Blocc. pallet laterale pos.car.1* Tras Acc.2*

      O     "M41.1";
      O     "M42.7";
      O     "M152.1";
      S     "EV146";
      R     "EV147";
NETWORK
TITLE =EV147 = Indietro Blocc. pallet laterale pos. car.1*Tras Acc.2*

      O     "M41.2";
      O     "M43.0";
      O     "M152.2";
      S     "EV147";
      R     "EV146";
NETWORK
TITLE =EV150 = Salita Fermo pallet frontale pos. car. 2* Tras Acc.2*

      O     "M41.6";
      O     "M43.4";
      O     "M152.6";
      S     "EV150";
      R     "EV151";
NETWORK
TITLE =EV151 = Discesa Fermo pallet frontale pos. car.2* Tras Acc.2*

      O     "M41.7";
      O     "M43.5";
      O     "M152.7";
      S     "EV151";
      R     "EV150";
NETWORK
TITLE =EV152 = Avanti Blocc. pallet frontale pos. car. 2 *Tras Acc.2*

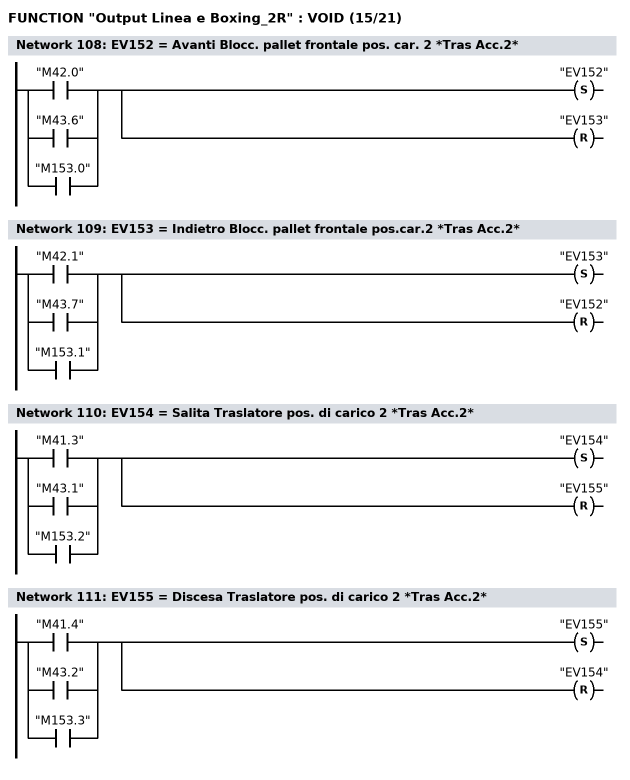
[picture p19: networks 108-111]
      O     "M42.0";
      O     "M43.6";
      O     "M153.0";
      S     "EV152";
      R     "EV153";
NETWORK
TITLE =EV153 = Indietro Blocc. pallet frontale pos.car.2 *Tras Acc.2*

      O     "M42.1";
      O     "M43.7";
      O     "M153.1";
      S     "EV153";
      R     "EV152";
NETWORK
TITLE =EV154 = Salita Traslatore pos. di carico 2 *Tras Acc.2*

      O     "M41.3";
      O     "M43.1";
      O     "M153.2";
      S     "EV154";
      R     "EV155";
NETWORK
TITLE =EV155 = Discesa Traslatore pos. di carico 2 *Tras Acc.2*

      O     "M41.4";
      O     "M43.2";
      O     "M153.3";
      S     "EV155";
      R     "EV154";
NETWORK
TITLE =HL156 = JOG + attivo accatastatrice 2 *Tras Acc.2*

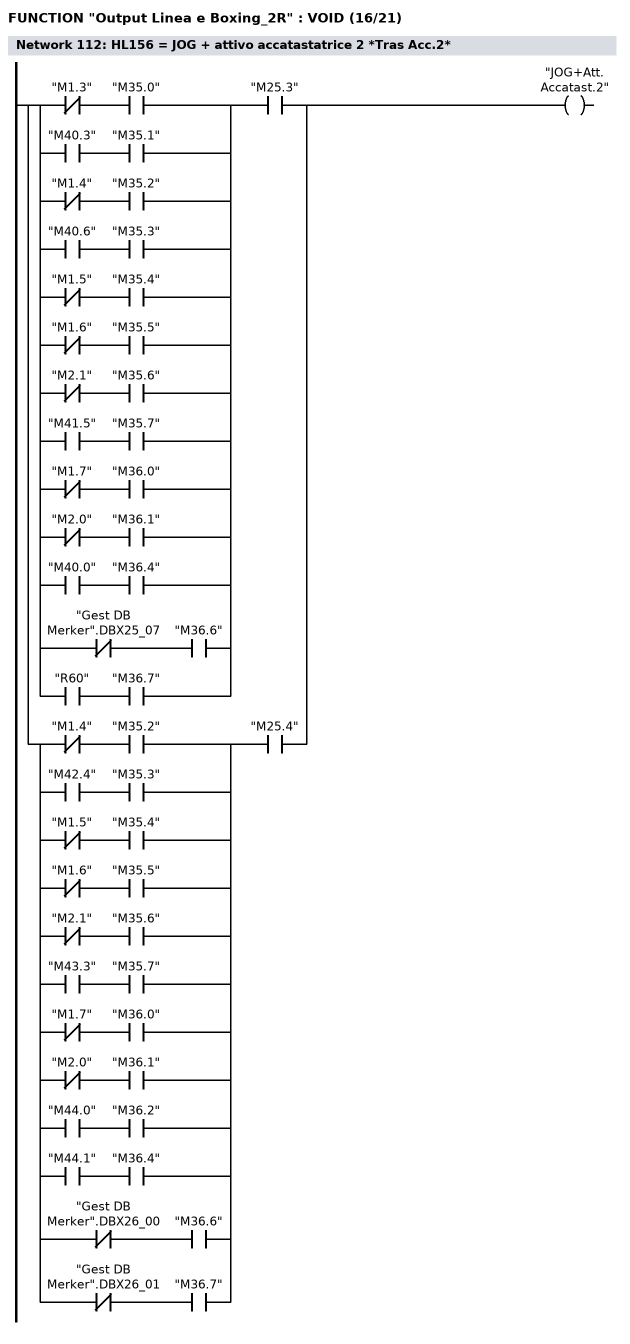
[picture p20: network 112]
      U(    ;
      UN    "M1.3";
      U     "M35.0";
      O     ;
      U     "M40.3";
      U     "M35.1";
      O     ;
      UN    "M1.4";
      U     "M35.2";
      O     ;
      U     "M40.6";
      U     "M35.3";
      O     ;
      UN    "M1.5";
      U     "M35.4";
      O     ;
      UN    "M1.6";
      U     "M35.5";
      O     ;
      UN    "M2.1";
      U     "M35.6";
      O     ;
      U     "M41.5";
      U     "M35.7";
      O     ;
      UN    "M1.7";
      U     "M36.0";
      O     ;
      UN    "M2.0";
      U     "M36.1";
      O     ;
      U     "M40.0";
      U     "M36.4";
      O     ;
      UN    "Gest DB Merker".DBX25_07;
      U     "M36.6";
      O     ;
      U     "R60";
      U     "M36.7";
      )     ;
      U     "M25.3";
      O     ;
      U(    ;
      UN    "M1.4";
      U     "M35.2";
      O     ;
      U     "M42.4";
      U     "M35.3";
      O     ;
      UN    "M1.5";
      U     "M35.4";
      O     ;
      UN    "M1.6";
      U     "M35.5";
      O     ;
      UN    "M2.1";
      U     "M35.6";
      O     ;
      U     "M43.3";
      U     "M35.7";
      O     ;
      UN    "M1.7";
      U     "M36.0";
      O     ;
      UN    "M2.0";
      U     "M36.1";
      O     ;
      U     "M44.0";
      U     "M36.2";
      O     ;
      U     "M44.1";
      U     "M36.4";
      O     ;
      UN    "Gest DB Merker".DBX26_00;
      U     "M36.6";
      O     ;
      UN    "Gest DB Merker".DBX26_01;
      U     "M36.7";
      )     ;
      U     "M25.4";
      =     "JOG+Att. Accatast.2";
NETWORK
TITLE =HL157 = JOG - attivo accatastatrice 2 * Traslatore Acc.2*

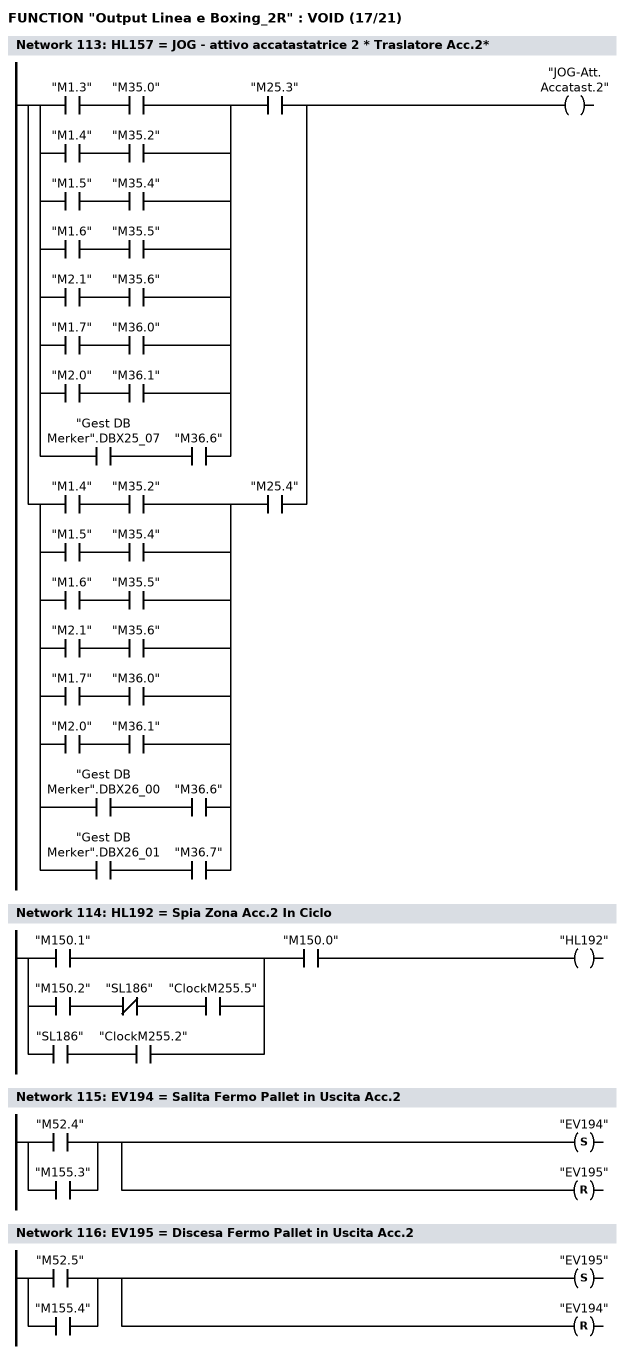
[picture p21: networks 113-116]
      U(    ;
      U     "M1.3";
      U     "M35.0";
      O     ;
      U     "M1.4";
      U     "M35.2";
      O     ;
      U     "M1.5";
      U     "M35.4";
      O     ;
      U     "M1.6";
      U     "M35.5";
      O     ;
      U     "M2.1";
      U     "M35.6";
      O     ;
      U     "M1.7";
      U     "M36.0";
      O     ;
      U     "M2.0";
      U     "M36.1";
      O     ;
      U     "Gest DB Merker".DBX25_07;
      U     "M36.6";
      )     ;
      U     "M25.3";
      O     ;
      U(    ;
      U     "M1.4";
      U     "M35.2";
      O     ;
      U     "M1.5";
      U     "M35.4";
      O     ;
      U     "M1.6";
      U     "M35.5";
      O     ;
      U     "M2.1";
      U     "M35.6";
      O     ;
      U     "M1.7";
      U     "M36.0";
      O     ;
      U     "M2.0";
      U     "M36.1";
      O     ;
      U     "Gest DB Merker".DBX26_00;
      U     "M36.6";
      O     ;
      U     "Gest DB Merker".DBX26_01;
      U     "M36.7";
      )     ;
      U     "M25.4";
      =     "JOG-Att. Accatast.2";
NETWORK
TITLE =HL192 = Spia Zona Acc.2 In Ciclo

      U(    ;
      O     "M150.1";
      O     ;
      U     "M150.2";
      UN    "SL186";
      U     "ClockM255.5";
      O     ;
      U     "SL186";
      U     "ClockM255.2";
      )     ;
      U     "M150.0";
      =     "HL192";
NETWORK
TITLE =EV194 = Salita Fermo Pallet in Uscita Acc.2

      O     "M52.4";
      O     "M155.3";
      S     "EV194";
      R     "EV195";
NETWORK
TITLE =EV195 = Discesa Fermo Pallet in Uscita Acc.2

      O     "M52.5";
      O     "M155.4";
      S     "EV195";
      R     "EV194";
NETWORK
TITLE =EV200 = Avanti fermo pallet in arrivo * Traslatore Acc.1*

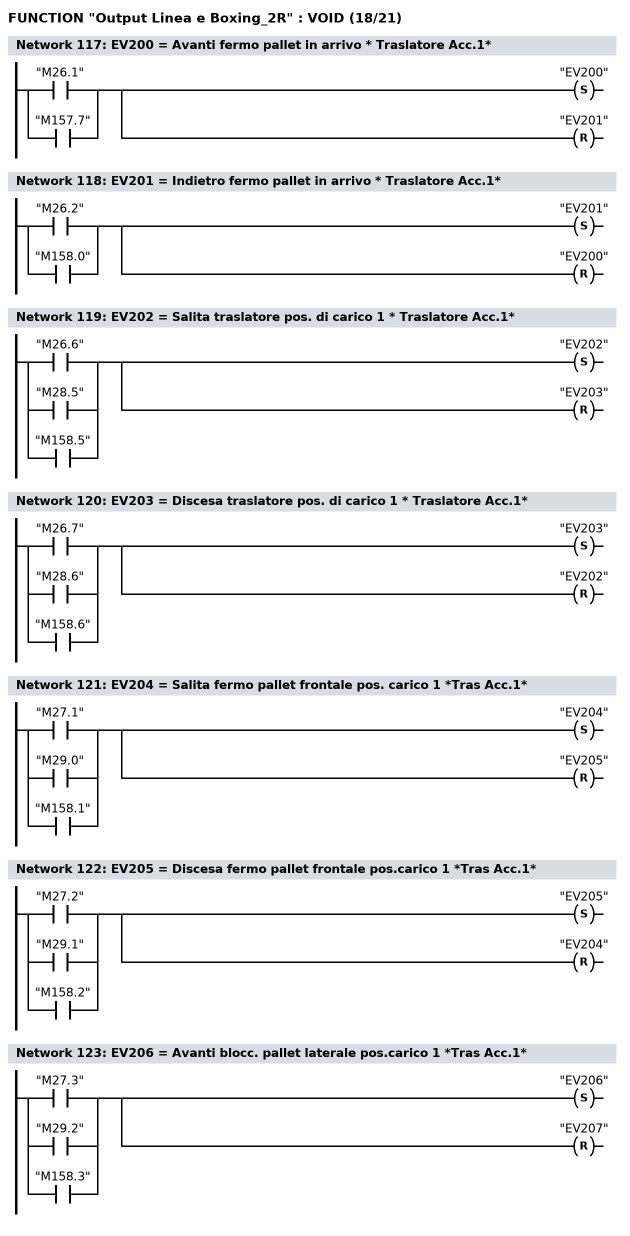
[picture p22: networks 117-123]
      O     "M26.1";
      O     "M157.7";
      S     "EV200";
      R     "EV201";
NETWORK
TITLE =EV201 = Indietro fermo pallet in arrivo * Traslatore Acc.1*

      O     "M26.2";
      O     "M158.0";
      S     "EV201";
      R     "EV200";
NETWORK
TITLE =EV202 = Salita traslatore pos. di carico 1 * Traslatore Acc.1*

      O     "M26.6";
      O     "M28.5";
      O     "M158.5";
      S     "EV202";
      R     "EV203";
NETWORK
TITLE =EV203 = Discesa traslatore pos. di carico 1 * Traslatore Acc.1*

      O     "M26.7";
      O     "M28.6";
      O     "M158.6";
      S     "EV203";
      R     "EV202";
NETWORK
TITLE =EV204 = Salita fermo pallet frontale pos. carico 1 *Tras Acc.1*

      O     "M27.1";
      O     "M29.0";
      O     "M158.1";
      S     "EV204";
      R     "EV205";
NETWORK
TITLE =EV205 = Discesa fermo pallet frontale pos.carico 1 *Tras Acc.1*

      O     "M27.2";
      O     "M29.1";
      O     "M158.2";
      S     "EV205";
      R     "EV204";
NETWORK
TITLE =EV206 = Avanti blocc. pallet laterale pos.carico 1 *Tras Acc.1*

      O     "M27.3";
      O     "M29.2";
      O     "M158.3";
      S     "EV206";
      R     "EV207";
NETWORK
TITLE =EV207 = Indietro blocc. pallet laterale pos.car. 1 *Tras Acc.1*

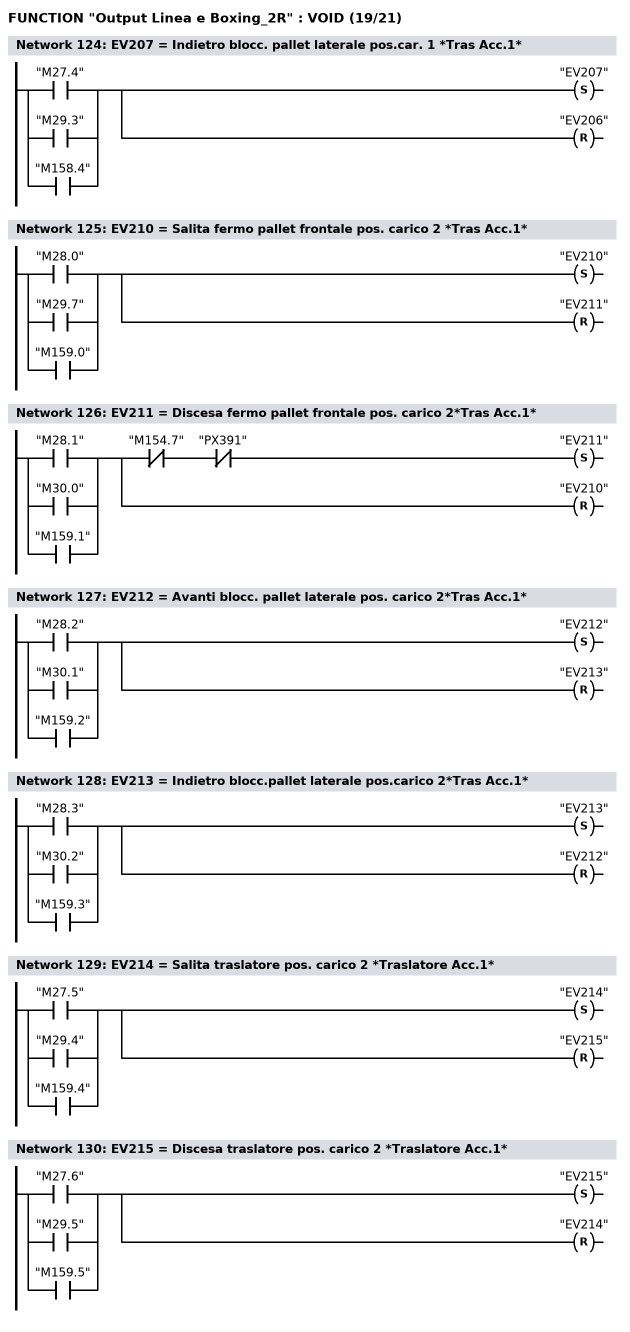
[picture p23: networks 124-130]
      O     "M27.4";
      O     "M29.3";
      O     "M158.4";
      S     "EV207";
      R     "EV206";
NETWORK
TITLE =EV210 = Salita fermo pallet frontale pos. carico 2 *Tras Acc.1*

      O     "M28.0";
      O     "M29.7";
      O     "M159.0";
      S     "EV210";
      R     "EV211";
NETWORK
TITLE =EV211 = Discesa fermo pallet frontale pos. carico 2*Tras Acc.1*

      O     "M28.1";
      O     "M30.0";
      O     "M159.1";
      =     L      0.0;
      U     L      0.0;
      UN    "M154.7";
      UN    "PX391";
      S     "EV211";
      U     L      0.0;
      BLD   102;
      R     "EV210";
NETWORK
TITLE =EV212 = Avanti blocc. pallet laterale pos. carico 2*Tras Acc.1*

      O     "M28.2";
      O     "M30.1";
      O     "M159.2";
      S     "EV212";
      R     "EV213";
NETWORK
TITLE =EV213 = Indietro blocc.pallet laterale pos.carico 2*Tras Acc.1*

      O     "M28.3";
      O     "M30.2";
      O     "M159.3";
      S     "EV213";
      R     "EV212";
NETWORK
TITLE =EV214 = Salita traslatore pos. carico 2 *Traslatore Acc.1*

      O     "M27.5";
      O     "M29.4";
      O     "M159.4";
      S     "EV214";
      R     "EV215";
NETWORK
TITLE =EV215 = Discesa traslatore pos. carico 2 *Traslatore Acc.1*

      O     "M27.6";
      O     "M29.5";
      O     "M159.5";
      S     "EV215";
      R     "EV214";
NETWORK
TITLE =EV216 = Salita fermo pallet in uscita * Traslatore Acc.1*

      O     "M26.4";
      O     "M157.5";
      S     "EV216";
      R     "EV217";
NETWORK
TITLE =EV217 = Discesa fermo pallet in uscita * Traslatore Acc.1*

      O     "M26.5";
      O     "M157.6";
      S     "EV217";
      R     "EV216";
NETWORK
TITLE =EV240 = Avanti primo fermo pallet da accat.2 *Traslatore Acc.1*

      O     "M30.6";
      O     "M154.2";
      S     "EV240";
      R     "EV241";
NETWORK
TITLE =EV241 = Indietro primo fermo pallet da accat.2 * Tras Acc.1*

      O     "M30.7";
      O     "M154.3";
      S     "EV241";
      R     "EV240";
NETWORK
TITLE =EV242 = Avanti secondo fermo pallet da accat.2 * Tras Acc.1*

      O     "M31.0";
      O     "M154.4";
      S     "EV242";
      R     "EV243";
NETWORK
TITLE =EV243 = Indietro secondo fermo pallet da accat. 2 * Tras Acc.1*

      O     "M31.1";
      O     "M154.5";
      S     "EV243";
      R     "EV242";
NETWORK
TITLE =EV244 = Avanti terzo fermo pallet da accat. 2 * Tras Acc.1*

      O     "M31.2";
      O     "M154.6";
      S     "EV244";
      R     "EV245";
NETWORK
TITLE =EV245 = Indietro terzo fermo pallet da accat. 3 * Tras Acc.1*

      O     "M31.3";
      O     "M154.7";
      S     "EV245";
      R     "EV244";
NETWORK
TITLE =Avanti Carro SX

      O     "MACS";
      O     "M92.1";
      O     "M94.3";
      O     "M96.5";
      S     "EV260";
      R     "EV261";
NETWORK
TITLE =Indietro Carro SX

      O     "MICS";
      O     "M93.2";
      O     "M95.4";
      O     "M97.6";
      S     "EV261";
      R     "EV260";
NETWORK
TITLE =Avanti Carro DX

      O     "MACD";
      O     "M82.1";
      O     "M84.3";
      O     "M86.5";
      S     "EV262";
      R     "EV263";
NETWORK
TITLE =Indietro Carro DX

      O     "MICD";
      O     "M83.2";
      O     "M85.4";
      O     "M87.6";
      S     "EV263";
      R     "EV262";
NETWORK
TITLE =Salita Scatola di Compressione SX

      O     "MSSDCS";
      O     "M93.1";
      O     "M93.6";
      O     "M95.3";
      O     "M95.7";
      O     "M97.5";
      O     "M98.1";
      O     "M225.7";
      O     "M231.7";
      O     "M237.7";
      O(    ;
      U(    ;
      UN    "SL710";
      U     "SL710B";
      U     "CSI";
      UN    "PX284";
      UN    "PX285";
      UN    "PX286";
      O(    ;
      U(    ;
      U     "PR637";
      FP    M    253.2;
      L     S5T#2S;
      SA    T     74;
      NOP   0;
      NOP   0;
      NOP   0;
      U     T     74;
      )     ;
      U     "CSI";
      )     ;
      )     ;
      UN    "MSSDCS";
      UN    "M93.1";
      UN    "M93.6";
      UN    "M95.3";
      UN    "M95.7";
      UN    "M97.5";
      UN    "M98.1";
      UN    "MDSDCS";
      UN    "M92.0";
      UN    "M92.5";
      UN    "M94.2";
      UN    "M94.6";
      UN    "M96.4";
      UN    "M97.0";
      )     ;
      =     "EV264";
NETWORK
TITLE =Discesa Scatola di Compressione SX

      O     "MDSDCS";
      O     "M92.0";
      O     "M92.5";
      O     "M94.2";
      O     "M94.6";
      O     "M96.4";
      O     "M97.0";
      =     "EV265";
NETWORK
TITLE =Salita Scatola di Compressione DX

      O     "MSSDCD";
      O     "M83.1";
      O     "M83.6";
      O     "M85.3";
      O     "M85.7";
      O     "M87.5";
      O     "M88.1";
      O     "M185.7";
      O     "M191.7";
      O     "M197.7";
      O(    ;
      U(    ;
      UN    "SL710";
      U     "SL710B";
      U     "CDI";
      UN    "PX287";
      UN    "PX290";
      UN    "PX291";
      O(    ;
      U(    ;
      U     "PR637";
      FP    M    253.3;
      L     S5T#2S;
      SA    T     75;
      NOP   0;
      NOP   0;
      NOP   0;
      U     T     75;
      )     ;
      U     "CDI";
      )     ;
      )     ;
      UN    "MSSDCD";
      UN    "M83.1";
      UN    "M83.6";
      UN    "M85.3";
      UN    "M85.7";
      UN    "M87.5";
      UN    "M88.1";
      UN    "MDSDCD";
      UN    "M82.0";
      UN    "M82.5";
      UN    "M84.2";
      UN    "M84.6";
      UN    "M86.4";
      UN    "M87.0";
      )     ;
      =     "EV266";
NETWORK
TITLE =Discesa Scatola di Compressione DX

      O     "MDSDCD";
      O     "M82.0";
      O     "M82.5";
      O     "M84.2";
      O     "M84.6";
      O     "M86.4";
      O     "M87.0";
      =     "EV267";
NETWORK
TITLE =Apertura supporti Pacco SX

      O     "MASPS";
      O     "M92.4";
      O     "M94.5";
      O     "M96.7";
      S     "EV270";
      R     "EV271";
NETWORK
TITLE =Chiusura supporti Pacco SX

      O     "MCSPS";
      O     "M93.5";
      O     "M95.6";
      O     "M98.0";
      S     "EV271";
      R     "EV270";
NETWORK
TITLE =Apertura Supporti Pacco DX

      O     "MASPD";
      O     "M82.4";
      O     "M84.5";
      O     "M86.7";
      S     "EV272";
      R     "EV273";
NETWORK
TITLE =Chiusura Supporti Pacco DX

      O     "MCSPD";
      O     "M83.5";
      O     "M85.6";
      O     "M88.0";
      S     "EV273";
      R     "EV272";
NETWORK
TITLE =EV320 = Discesa fermo pallet in uscita * Zona Piega bandiere*

      O     "M34.3";
      O     "M166.2";
      S     "EV320";
      R     "EV321";
NETWORK
TITLE =EV321 = Salita fermo pallet in uscita * Zona Piega bandiere *

      O     "M34.2";
      O     "M166.1";
      S     "EV321";
      R     "EV320";
NETWORK
TITLE =EV322 = Discesa fermo pallet in arrivo * Zona ascensore C.O.S.*

      U     "M166.4";
      L     S5T#1S;
      SE    T     77;
NETWORK
TITLE =EV323 = Salita fermo pallet in arrivo * Zona ascensore C.O.S. *

      O     "M34.5";
      O     ;
      U     "M166.4";
      U     T     77;
      S     "EV322";
      R     "EV323";
NETWORK
TITLE =EV324 = Discesa fermo pallet sotto Piega * Zona Piega bandiere*

      O     "M34.4";
      O     "M166.3";
      S     "EV323";
      R     "EV322";
NETWORK
TITLE =EV325 = Salita fermo pallet sotto Piega * Zona Piega bandiere *

      O     "M33.5";
      O     "M165.4";
      S     "EV324";
      R     "EV325";
NETWORK
TITLE =EV326 = Discesa piega bandiere * Zona Piega bandiere *

      O     "M33.4";
      O     "M165.3";
      S     "EV325";
      R     "EV324";
NETWORK
TITLE =EV327 = Salita piega bandiere * Zona Piega bandiere *

      O     "M33.7";
      O     "M165.5";
      S     "EV326";
      R     "EV327";
NETWORK
TITLE =EV330 = Avanti piega bandiere * Zona Piega bandiere *

      O     "M33.6";
      O     "M165.6";
      S     "EV327";
      R     "EV326";
NETWORK
TITLE =EV331 = Indietro piega bandiere * Zona Piega bandiere *

      O     "M34.0";
      O     "M165.7";
      S     "EV330";
      R     "EV331";
NETWORK
TITLE =EV332 = Discesa Fermo pallet in arrivo  * Zona Piega Bandiere *

      O     "M34.1";
      O     "M166.0";
      S     "EV331";
      R     "EV330";
NETWORK
TITLE =EV333 = Salita Fermo pallet in arrivo * Zona Piega Bandiere *

      O     "M33.3";
      O     "M165.2";
      S     "EV332";
      R     "EV333";
NETWORK
TITLE =EV334 = Discesa fermo pallet su chiusura * Zona All. *

      O     "M33.2";
      O     "M165.1";
      S     "EV333";
      R     "EV332";
NETWORK
TITLE =EV335 = Salita fermo pallet su chiusura * Zona All. *

      O     "M32.1";
      O     "M162.6";
      S     "EV334";
      R     "EV335";
NETWORK
TITLE =EV336 = Discesa Chiusura pallet * Zona allineamento bandiere *

      O     "M32.0";
      O     "M162.5";
      S     "EV335";
      R     "EV334";
NETWORK
TITLE =EV337 = Salita Chiusura pallet * Zona allineamento bandiere *

      O     "M32.7";
      O     "M164.2";
      =     L      0.0;
      U     L      0.0;
      BLD   102;
      S     "EV336";
      U     L      0.0;
      U(    ;
      O     "FM426";
      O     "M32.7";
      )     ;
      R     "EV337";
NETWORK
TITLE =EV340 = Avanti allineamento pacchi * Zona Allineamento *

      O     "M32.6";
      O     "M164.0";
      S     "EV337";
      R     "EV336";
NETWORK
TITLE =EV341 = Indietro allineamento pacchi * Zona allineamento *

      O     "M32.2";
      O     "M162.7";
      S     "EV340";
      R     "EV341";
NETWORK
TITLE =EV342 = Chiusura allineamento  bandiere * Zona All. *

      UN    "M32.2";
      U     "JOG-Acc1-ZB";
      U     "M20.3";
      U     "M25.2";
      O     "M163.0";
      S     "EV341";
      R     "EV340";
NETWORK
TITLE =EV343 = Apertura allineamento  bandiere * Zona All. *

      O     "M32.5";
      O     "M163.3";
      S     "EV342";
      R     "EV343";
NETWORK
TITLE =EV344 = Discesa fermo pallet in arrivo * Zona Allineamento *

      UN    "M32.5";
      U     "JOG-Acc1-ZB";
      U     "M20.5";
      U     "M25.2";
      O     "M163.4";
      S     "EV343";
      R     "EV342";
NETWORK
TITLE =EV345 = Salita fermo pallet in arrivo * Zona Allineamento *

      O     "M31.6";
      O     "M162.4";
      S     "EV344";
      R     "EV345";
NETWORK
TITLE =EV346 = Discesa allineamento bandiere * Zona Allineamento *

      O     "M31.5";
      O     "M162.3";
      S     "EV345";
      R     "EV344";
NETWORK
TITLE =EV347 = Salita allineamento bandiere * Zona Allineamento *

      O     "M32.3";
      O     "M163.1";
      S     "EV346";
      R     "EV347";
NETWORK
TITLE =EV350 =

      O     "M32.4";
      O     "M163.2";
      S     "EV347";
      R     "EV346";
NETWORK
TITLE =EV351 =

      CLR   ;
      =     "EV350";
NETWORK
TITLE =EV352 = Salita Fermo pallet Anteriore su Ascensore Carico C.O.S

      CLR   ;
      =     "EV351";
NETWORK
TITLE =EV353 = Discesa Fermo pallet Anteriore su Ascensore Carico C.O.S

      O     "M166.6";
      O     "M52.0";
      O     "M180.2";
      S     "EV352";
      R     "EV353";
NETWORK
TITLE =EV354 = Salita Fermo pallet Posteriore su Ascensore Caric C.O.S

      O     "M166.7";
      O     "M52.1";
      O     "M180.0";
      S     "EV353";
      R     "EV352";
NETWORK
TITLE =EV355 = Discesa Fermo pallet Posteriore su Ascensore Caric C.O.S

      O     "M167.0";
      O     "M52.2";
      O     "M180.3";
      S     "EV354";
      R     "EV355";
NETWORK
TITLE =Scorta

      O     "M167.1";
      O     "M52.3";
      S     "EV355";
      R     "EV354";
NETWORK
TITLE =Scorta

      CLR   ;
      =     "A      35.6";
NETWORK
TITLE =HL422 = JOG + attivo * Traslatore Acc. 1 o Zona bandiere *

      CLR   ;
      =     "A      35.7";
NETWORK
TITLE =HL423 = JOG  - attivo * Traslatore Acc. 1 o Zona bandiere *

      U(    ;
      U     "M26.0";
      U     "M20.0";
      O     ;
      UN    "M0.0";
      U     "M20.1";
      O     ;
      U     "M26.3";
      U     "M20.2";
      O     ;
      UN    "M0.7";
      U     "M20.3";
      O     ;
      UN    "M0.1";
      U     "M20.4";
      O     ;
      U     "M27.0";
      U     "M20.5";
      O     ;
      UN    "M0.2";
      U     "M20.6";
      O     ;
      UN    "M0.3";
      U     "M20.7";
      O     ;
      UN    "M0.6";
      U     "M21.0";
      O     ;
      U     "M27.7";
      U     "M21.1";
      O     ;
      UN    "M0.4";
      U     "M21.2";
      O     ;
      UN    "M0.5";
      U     "M21.3";
      O     ;
      U     "M28.4";
      U     "M21.4";
      )     ;
      U     "M25.0";
      O     ;
      U(    ;
      U     "M30.5";
      U     "M20.1";
      O     ;
      UN    "M0.1";
      U     "M20.4";
      O     ;
      U     "M28.7";
      U     "M20.5";
      O     ;
      UN    "M0.2";
      U     "M20.6";
      O     ;
      UN    "M0.3";
      U     "M20.7";
      O     ;
      UN    "M0.6";
      U     "M21.0";
      O     ;
      U     "M29.6";
      U     "M21.1";
      O     ;
      UN    "M0.4";
      U     "M21.2";
      O     ;
      UN    "M0.5";
      U     "M21.3";
      O     ;
      U     "M30.3";
      U     "M21.4";
      O     ;
      U     "M30.4";
      U     "M21.5";
      O     ;
      UN    "M1.0";
      U     "M21.6";
      O     ;
      UN    "M1.1";
      U     "M21.7";
      O     ;
      UN    "M1.2";
      U     "M22.0";
      )     ;
      U     "M25.1";
      O     ;
      U(    ;
      UN    "M7.1";
      U     "M20.0";
      O     ;
      U     "M31.7";
      U     "M20.1";
      O     ;
      U     "M9.2";
      U     "M20.2";
      O     ;
      UN    "M7.0";
      UN    "M2.7";
      U     "M20.3";
      O     ;
      U     "M2.3";
      U     "M20.4";
      O     ;
      U     "M2.4";
      U     "M2.6";
      U     "M20.5";
      O     ;
      UN    "M9.3";
      U     "M20.6";
      O     ;
      U     "M54.0";
      U     "M20.7";
      O     ;
      UN    "M7.2";
      U     "M21.0";
      O     ;
      UN    "M7.3";
      U     "M21.1";
      O     ;
      U     "M7.7";
      U     "M21.2";
      O     ;
      UN    "M8.0";
      UN    "M8.1";
      U     "M21.3";
      O     ;
      UN    "M7.4";
      U     "M21.4";
      O     ;
      U     "M31.4";
      U     "M21.5";
      O     ;
      UN    "M7.5";
      U     "M21.6";
      O     ;
      U     "M34.6";
      U     "M21.7";
      O     ;
      UN    "M54.1";
      U     "M22.0";
      O     ;
      UN    "M54.2";
      U     "M22.1";
      )     ;
      U     "M25.2";
      =     "JOG+Att. Accatast.1-ZB";
NETWORK
TITLE =HL436 = Spia Zona Bandiere In Ciclo

      U(    ;
      U     "M0.0";
      U     "M20.1";
      O     ;
      U     "M0.7";
      U     "M20.3";
      O     ;
      U     "M0.1";
      U     "M20.4";
      O     ;
      U     "M0.2";
      U     "M20.6";
      O     ;
      U     "M0.3";
      U     "M20.7";
      O     ;
      U     "M0.6";
      U     "M21.0";
      O     ;
      U     "M0.4";
      U     "M21.2";
      O     ;
      U     "M0.5";
      U     "M21.3";
      )     ;
      U     "M25.0";
      O     ;
      U(    ;
      U     "M0.1";
      U     "M20.4";
      O     ;
      U     "M0.2";
      U     "M20.6";
      O     ;
      U     "M0.3";
      U     "M20.7";
      O     ;
      U     "M0.6";
      U     "M21.0";
      O     ;
      U     "M0.4";
      U     "M21.2";
      O     ;
      U     "M0.5";
      U     "M21.3";
      O     ;
      U     "M1.0";
      U     "M21.6";
      O     ;
      U     "M1.1";
      U     "M21.7";
      O     ;
      U     "M1.2";
      U     "M22.0";
      )     ;
      U     "M25.1";
      O     ;
      U(    ;
      U     "M7.1";
      U     "M20.0";
      O     ;
      U     "M9.5";
      U     "M20.2";
      O     ;
      U     "M7.0";
      U     "M2.7";
      U     "M20.3";
      O     ;
      U     "M2.2";
      U     "M20.4";
      O     ;
      U     "M2.5";
      U     "M19.7";
      U     "M20.5";
      O     ;
      U     "M9.3";
      U     "M20.6";
      O     ;
      U     "M9.4";
      U     "M20.7";
      O     ;
      U     "M7.2";
      U     "M21.0";
      O     ;
      U     "M7.3";
      U     "M21.1";
      O     ;
      U     "M7.6";
      U     "M21.2";
      O     ;
      U     "M8.0";
      U     "M8.1";
      U     "M21.3";
      O     ;
      U     "M7.4";
      U     "M21.4";
      O     ;
      U     "M7.5";
      U     "M21.6";
      O     ;
      U     "M34.7";
      U     "M21.7";
      O     ;
      U     "M54.1";
      U     "M22.0";
      O     ;
      U     "M54.2";
      U     "M22.1";
      )     ;
      U     "M25.2";
      =     "JOG-Att. Accatast.1-ZB";
NETWORK
TITLE =HL437 = Spia Zona Acc.1 In Ciclo

      U(    ;
      O     "M161.1";
      O     ;
      U     "M161.2";
      UN    "SL434";
      U     "ClockM255.5";
      O     ;
      U     "SL434";
      U     "ClockM255.2";
      )     ;
      U     "M161.0";
      =     "HL436";
NETWORK
TITLE =

      U(    ;

      O     "M156.1";
      O     ;
      U     "M156.2";
      UN    "SL430";
      U     "ClockM255.5";
      O     ;
      U     "SL430";
      U     "ClockM255.2";
      )     ;
      U     "M156.0";
      =     "HL437";
NETWORK
TITLE =

      U     DB98.DBX   17.2;
      SPBN  M001;
      L     3;
      T     "prova".DB_VAR2;
      SPA   M002;
M001: L     0;
      T     "prova".DB_VAR2;
M002: NOP   0;

NETWORK
TITLE =

      UC    FC   105;

END_FUNCTION

